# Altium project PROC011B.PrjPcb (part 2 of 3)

## Sheet PROC011B_PMIC.SchDoc: PMIC
size 431 x 279 mm; Date: Not shown in title block; ApprovedBy: Not shown in title block; CheckedBy: Not shown in title block; Author: Not shown in title block; CompanyName: Not shown in title block; Engineer: Not shown in title block; Organization: Not shown in title block; Address1: Not shown in title block; Address2: Not shown in title block; Address3: Not shown in title block; Address4: Not shown in title block; DocumentNumber: 1; Revision: Use project parameter SCH_Rev; SheetNumber: 8; SheetTotal: 17; PageSetup: Record=PageOptions¦CenterHorizontal=True¦CenterVertical=True¦PrintScale=1.00¦XCorrection=1.00¦YCorrection=1.00¦PrintKind=0¦BorderSize=5000000¦LeftOffset=0¦BottomOffset=0¦Orientation=2¦PaperLength=1000¦PaperWidth=1000¦Scale=100¦PaperSource=15¦PrintQuality=600¦MediaType=1¦DitherType=10¦PaperKind=Letter¦PrintScaleMode=1

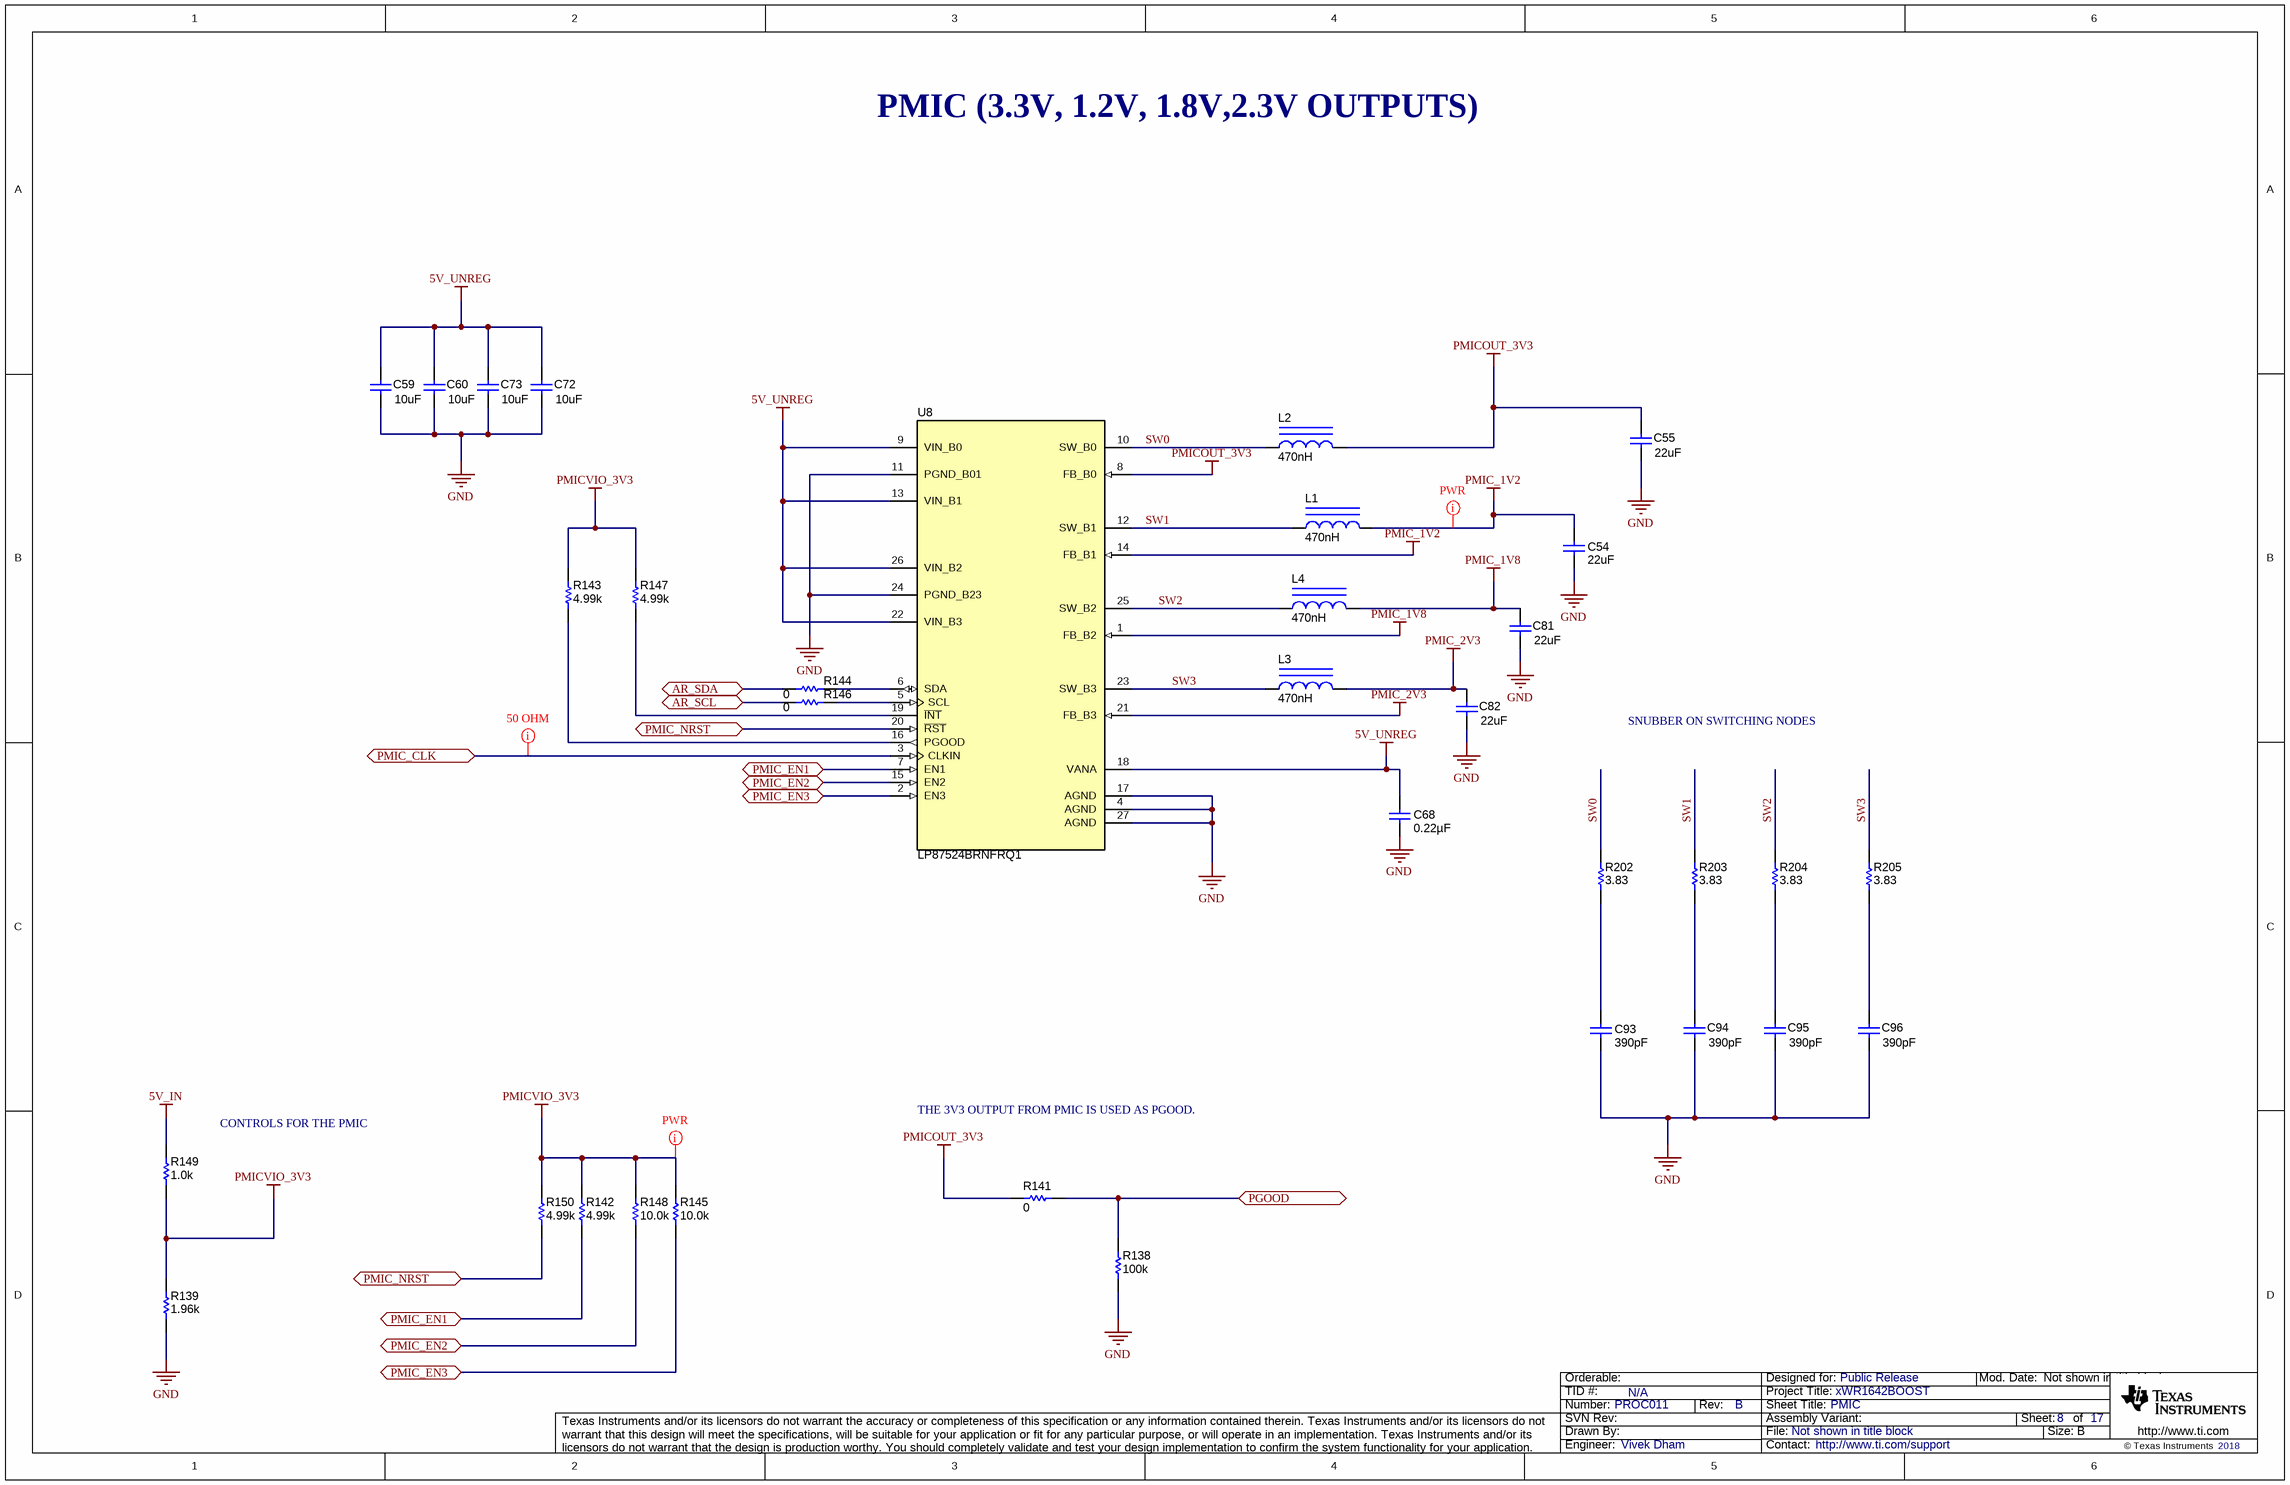
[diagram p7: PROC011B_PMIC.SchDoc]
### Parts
C54  ValueDisplayed: 22uF  [1206_180]  (hidden comment: GCM31CR71A226KE02)
C55  ValueDisplayed: 22uF  [1206_180]  (hidden comment: GCM31CR71A226KE02)
C59  ValueDisplayed: 10uF  [0805_HV]  (hidden comment: GCM21BR71A106KE22L)
C60  ValueDisplayed: 10uF  [0805_HV]  (hidden comment: GCM21BR71A106KE22L)
C68  ValueDisplayed: 0.22µF  [0402L]  (hidden comment: GCM155R71C224KE02D)
C72  ValueDisplayed: 10uF  [0805_HV]  (hidden comment: GCM21BR71A106KE22L)
C73  ValueDisplayed: 10uF  [0805_HV]  (hidden comment: GCM21BR71A106KE22L)
C81  ValueDisplayed: 22uF  [1206_180]  (hidden comment: GCM31CR71A226KE02)
C82  ValueDisplayed: 22uF  [1206_180]  (hidden comment: GCM31CR71A226KE02)
C93  ValueDisplayed: 390pF  [0402L]  (hidden comment: CGA2B2NP01H391J050BA)
C94  ValueDisplayed: 390pF  [0402L]  (hidden comment: CGA2B2NP01H391J050BA)
C95  ValueDisplayed: 390pF  [0402L]  (hidden comment: CGA2B2NP01H391J050BA)
C96  ValueDisplayed: 390pF  [0402L]  (hidden comment: CGA2B2NP01H391J050BA)
L1  ValueDisplayed: 470nH  [DFE252012P]  (hidden comment: DFE252012P-R47M=P2)
L2  ValueDisplayed: 470nH  [DFE252012P]  (hidden comment: DFE252012P-R47M=P2)
L3  ValueDisplayed: 470nH  [DFE252012P]  (hidden comment: DFE252012P-R47M=P2)
L4  ValueDisplayed: 470nH  [DFE252012P]  (hidden comment: DFE252012P-R47M=P2)
R138  ValueDisplayed: 100k  [0402L]  (hidden comment: CRCW0402100KFKED)
R139  ValueDisplayed: 1.96k  [0402L]  (hidden comment: CRCW04021K96FKED)
R141  ValueDisplayed: 0  [0402L]  (hidden comment: ERJ-2GE0R00X)
R142  ValueDisplayed: 4.99k  [0402L]  (hidden comment: ERJ-2RKF4991X)
R143  ValueDisplayed: 4.99k  [0402L]  (hidden comment: CRCW04024K99FKED)
R144  ValueDisplayed: 0  [0201_Silk]  (hidden comment: CRCW02010000Z0ED)
R145  ValueDisplayed: 10.0k  [0402L]  (hidden comment: CRCW040210K0FKED)
R146  ValueDisplayed: 0  [0201_Silk]  (hidden comment: CRCW02010000Z0ED)
R147  ValueDisplayed: 4.99k  [0402L]  (hidden comment: CRCW04024K99FKED)
R148  ValueDisplayed: 10.0k  [0402L]  (hidden comment: CRCW040210K0FKED)
R149  ValueDisplayed: 1.0k  [0402L]  (hidden comment: ERJ-2GEJ102X)
R150  ValueDisplayed: 4.99k  [0402L]  (hidden comment: ERJ-2RKF4991X)
R202  ValueDisplayed: 3.83  [0402L]  (hidden comment: CRCW04023R83FKED)
R203  ValueDisplayed: 3.83  [0402L]  (hidden comment: CRCW04023R83FKED)
R204  ValueDisplayed: 3.83  [0402L]  (hidden comment: CRCW04023R83FKED)
R205  ValueDisplayed: 3.83  [0402L]  (hidden comment: CRCW04023R83FKED)
U8  LP87524BRNFRQ1  [RNF0026C]

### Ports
AR_SCL, AR_SDA, PGOOD, PMIC_CLK, PMIC_EN1, PMIC_EN2, PMIC_EN3, PMIC_NRST

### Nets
5V_IN: R149.2
5V_UNREG: C59.2 C60.2 C68.2 C72.2 C73.2 U8.9(VIN_B0) U8.13(VIN_B1) U8.18(VANA) U8.22(VIN_B3) U8.26(VIN_B2)
GND: C54.1 C55.1 C59.1 C60.1 C68.1 C72.1 C73.1 C81.1 C82.1 C93.1 C94.1 C95.1 C96.1 R138.1 R139.1 U8.4(AGND) U8.11(PGND_B01) U8.17(AGND) U8.24(PGND_B23) U8.27(AGND)
PMIC_1V2: C54.2 L1.2 U8.14(FB_B1)
PMIC_1V8: C81.2 L4.2 U8.1(FB_B2)
PMIC_2V3: C82.2 L3.2 U8.21(FB_B3)
PMICOUT_3V3: C55.2 L2.2 R141.1 U8.8(FB_B0)
PMICVIO_3V3: R139.2 R142.2 R143.2 R145.2 R147.2 R148.2 R149.1 R150.1
AR_SCL: R146.1 ; port AR_SCL
AR_SDA: R144.2 ; port AR_SDA
PGOOD: R138.2 R141.2 ; port PGOOD
PMIC_CLK: U8.3(CLKIN) ; port PMIC_CLK
PMIC_EN1: R142.1 U8.7(EN1) ; port PMIC_EN1
PMIC_EN2: R148.1 U8.15(EN2) ; port PMIC_EN2
PMIC_EN3: R145.1 U8.2(EN3) ; port PMIC_EN3
PMIC_NRST: R150.2 U8.20(~{RST}) ; port PMIC_NRST
SW0: L2.1 R202.2 U8.10(SW_B0)
SW1: L1.1 R203.2 U8.12(SW_B1)
SW2: L4.1 R204.2 U8.25(SW_B2)
SW3: L3.1 R205.2 U8.23(SW_B3)
NetC93_2: C93.2 R202.1
NetC94_2: C94.2 R203.1
NetC95_2: C95.2 R204.1
NetC96_2: C96.2 R205.1
NetR143_1: R143.1 U8.16(PGOOD)
NetR144_1: R144.1 U8.6(SDA)
NetR146_2: R146.2 U8.5(SCL)
NetR147_1: R147.1 U8.19(~{INT})

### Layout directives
net class 50_OHM: PMIC_CLK
net class PWR: PMIC_1V2, PMICVIO_3V3

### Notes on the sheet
- PMIC (3.3V, 1.2V, 1.8V,2.3V OUTPUTS)
- SNUBBER ON SWITCHING NODES
- CONTROLS FOR THE PMIC
- THE 3V3 OUTPUT FROM PMIC IS USED AS PGOOD.

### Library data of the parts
C54 = CMP-0008811-2: CAP, CERM, 22 uF, 10 V, +/- 10%, X7R, AEC-Q200 Grade 1, 1206; Manufacturer: MuRata; TaMin_C: -55°C; Polarized: N; SizeAreaWB_mm2: 10.92; Value1: Unknown; U/M: EA; Value: 22uF; TaMax_C: 125°C; SizeZ_mm: 1.8; SizeX_mm: 3.2; SizeY_mm: 1.6; Cap_Case: 1206; Value2: 10V; SizeArea_mm2: 5.12; CompType: Capacitor; AEC Qualified: Y; Cap_F: 22µF; AEC Grade: 1; AEC Category: Q200
C55 C81 C82 = CMP-0008811-2: CAP, CERM, 22 uF, 10 V, +/- 10%, X7R, AEC-Q200 Grade 1, 1206; Manufacturer: MuRata; TaMin_C: -55°C; Polarized: N; SizeAreaWB_mm2: 10.92; Value1: Unknown; U/M: EA; Value: 22uF; TaMax_C: 125°C; SizeZ_mm: 1.8; SizeX_mm: 3.2; SizeY_mm: 1.6; Cap_Case: 1206; Value2: 10V; SizeArea_mm2: 5.12; AEC Qualified: Y; Cap_F: 22µF; AEC Grade: 1; AEC Category: Q200
C59 C60 C72 C73 = CMP-0008017-2: CAP, CERM, 10 uF, 10 V, +/- 10%, X7R, 0805; Manufacturer: MuRata; TaMin_C: -55°C; Polarized: N; SizeAreaWB_mm2: 6.75; Value1: Unknown; U/M: EA; Value: 10uF; TaMax_C: 125°C; SizeZ_mm: 1.45; SizeX_mm: 2; SizeY_mm: 1.25; Cap_Case: 0805; Value2: 10V; SizeArea_mm2: 2.5; CompType: Capacitor; Cap_F: 10µF; AEC Category: Q200
C68 = CMP-0078265-1: CAP, CERM, 0.22 µF, 16 V,+/- 10%, X7R, AEC-Q200 Grade 1, 0402; Manufacturer: MuRata; TaMin_C: -55°C; Polarized: N; SizeAreaWB_mm2: 3; U/M: EA; Value: 0.22uF; TaMax_C: 125°C; SizeZ_mm: 0.6; SizeX_mm: 1; SizeY_mm: 0.5; Cap_Case: 0402; Value2: 16V; CompType: Capacitor; AEC Qualified: Y; Cap_F: 220nF; AEC Category: Q200
C93-C96 = CMP-0078223-1: CAP, CERM, 390 pF, 50 V,+/- 5%, C0G/NP0, AEC-Q200 Grade 0, 0402; Manufacturer: TDK; TaMin_C: -55°C; Polarized: N; SizeAreaWB_mm2: 3; U/M: EA; Value: 390pF; TaMax_C: 150°C; SizeZ_mm: 0.6; SizeX_mm: 1; SizeY_mm: 0.5; Cap_Case: 0402; Value2: 50V; AEC Qualified: Y; AEC Grade: 0; AEC Category: Q200
L1-L4 = CMP-0058946-1: Inductor, Shielded, 470 nH, 4.7 A, 0.021 ohm, SMD; Manufacturer: MuRata Toko; Isat: 6.4A @ 30% inductance drop; Irms: 4.7A @ 40C rise; SizeAreaWB_mm2: 10.5; DCR_ohm: 0.021; Value: 470nH; Imax_A: 4.7A; SizeZ_mm: 1.2; SizeX_mm: 2.5; SizeY_mm: 2; SizeArea_mm2: 5; AEC Category: Q200
R138 = CMP-0025950-2: RES, 100 k, 1%, 0.063 W, 0402; Manufacturer: Vishay-Dale; Power_W: 63mW; TempCo: 100 ppm/C; U/M: EA; Value: 100k; EIA_Code: E96; SizeX_mm: 1; SizeY_mm: 0.5; SizeZ_mm: 0.6; Value2: 0.063W; VDC_V: 50V; AEC Category: Q200
R139 = CMP-0026099-1: RES, 1.96 k, 1%, 0.063 W, 0402; Manufacturer: Vishay-Dale; Power_W: 63mW; TempCo: 100 ppm/C; Value_Code: 1k96; U/M: EA; Value: 1.96k; EIA_Code: E96; SizeX_mm: 1; SizeY_mm: 0.5; SizeZ_mm: 0.6; Value2: 0.063W; CompType: Resistor; VDC_V: 50V; AEC Category: Q200
R141 = CMP-0026992-2: RES, 0, 5%, 0.063 W, 0402; Manufacturer: Panasonic; Power_W: 63mW; TempCo: 600 ppm/C; Value_Code: 0000; U/M: EA; Value: 0; EIA_Code: E24; SizeX_mm: 1; SizeY_mm: 0.5; SizeZ_mm: 0.6; Value2: 0.063W; VDC_V: 50V; AEC Category: Q200
R142 R150 = CMP-0026701-1: RES, 4.99 k, 1%, 0.1 W, AEC-Q200 Grade 0, 0402; Manufacturer: Panasonic; Power_W: 100mW; TempCo: 100 ppm/C; Value_Code: 4k99; U/M: EA; Value: 4.99k; EIA_Code: E96; SizeX_mm: 1; SizeY_mm: 0.5; SizeZ_mm: 0.6; Value2: 0.1W; AEC Qualified: Y; VDC_V: 50V; AEC Grade: 0; AEC Category: Q200
R143 R147 = CMP-0026414-1: RES, 4.99 k, 1%, 0.063 W, 0402; Manufacturer: Vishay-Dale; Power_W: 63mW; TempCo: 100 ppm/C; Value_Code: 4k99; U/M: EA; Value: 4.99k; EIA_Code: E96; SizeX_mm: 1; SizeY_mm: 0.5; SizeZ_mm: 0.6; Value2: 0.063W; VDC_V: 50V; AEC Category: Q200
R144 R146 = CMP-0027008-3: RES, 0, 5%, 0.05 W, 0201; Manufacturer: Vishay-Dale; Power_W: 50mW; TempCo: ppm/C; Value_Code: 0000; U/M: EA; Value: 0; EIA_Code: E24; SizeX_mm: 0.6; SizeY_mm: 0.3; SizeZ_mm: 0.26; Value2: 0.05W; SizeArea_mm2: 0.18; AEC Qualified: N; AEC Category: Q200
R145 R148 = CMP-0025958-2: RES, 10.0 k, 1%, 0.063 W, 0402; Manufacturer: Vishay-Dale; Power_W: 63mW; TempCo: 100 ppm/C; Value_Code: 10k0; U/M: EA; Value: 10.0k; EIA_Code: E96; Res_ohm: 10k; SizeX_mm: 1; SizeY_mm: 0.5; SizeZ_mm: 0.6; Value2: 0.063W; VDC_V: 50V; AEC Category: Q200
R149 = CMP-0078193-1: RES, 1.0 k, 5%, 0.1 W, AEC-Q200 Grade 0, 0402; Manufacturer: Panasonic; Value_Code: 1k00; SizeArea_mm2: 0.5; AEC Qualified: Y; AEC Category: Q200; Res_ohm: 1k; Value: 1.0k; SizeZ_mm: 0.6; Green_REACh: Passed; EIA_Code: E24; TempCo: 200 ppm/C; AEC Grade: 0; Power_W: 100mW; VDC_V: 50V; Value2: 0.1W; Green_Lifecycle: Active; U/M: EA; SizeX_mm: 1
R202-R205 = CMP-0026363-1: RES, 3.83, 1%, 0.063 W, 0402; Manufacturer: Vishay-Dale; Power_W: 63mW; TempCo: 100 ppm/C; Value_Code: 3R83; U/M: EA; Value: 3.83; EIA_Code: E96; SizeX_mm: 1; SizeY_mm: 0.5; SizeZ_mm: 0.6; Value2: 0.063W; VDC_V: 50V; AEC Category: Q200
U8 = CMP-0013883-2: Four-Phase 2.5-A-per-Phase Buck Converter With Integrated Switches, RNF0026C (VQFN-HR-26); Manufacturer: Texas Instruments; SizeX_mm: 4; SizeY_mm: 4.5; CompType: IC; SizeZ_mm: 0.9; SizeArea_mm2: 18; SizeAreaWB_mm2: 27.5; U/M: EA

## Sheet PROC011B_QSPI flash section.SchDoc: QSPI flash section
size 431 x 279 mm; Date: Not shown in title block; ApprovedBy: Not shown in title block; CheckedBy: Not shown in title block; Author: Not shown in title block; CompanyName: Not shown in title block; Engineer: Not shown in title block; Organization: Not shown in title block; Address1: Not shown in title block; Address2: Not shown in title block; Address3: Not shown in title block; Address4: Not shown in title block; DocumentNumber: 1; Revision: Use project parameter SCH_Rev; SheetNumber: 9; SheetTotal: 17; PageSetup: Record=PageOptions¦CenterHorizontal=True¦CenterVertical=True¦PrintScale=1.00¦XCorrection=1.00¦YCorrection=1.00¦PrintKind=0¦BorderSize=5000000¦LeftOffset=0¦BottomOffset=0¦Orientation=2¦PaperLength=1000¦PaperWidth=1000¦Scale=100¦PaperSource=15¦PrintQuality=600¦MediaType=1¦DitherType=10¦PaperKind=Letter¦PrintScaleMode=1

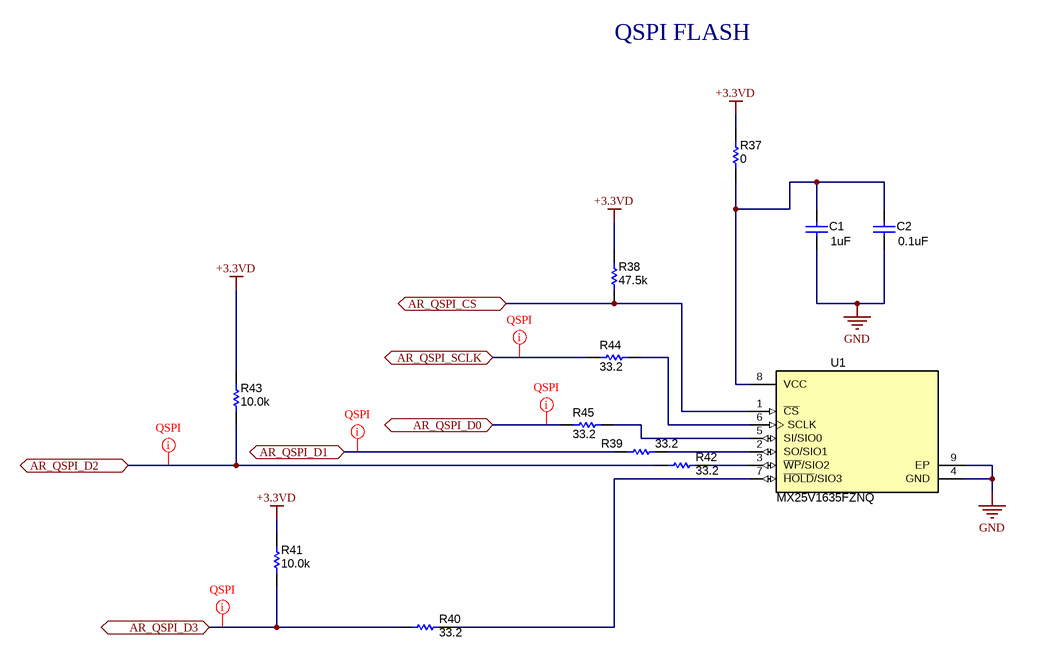
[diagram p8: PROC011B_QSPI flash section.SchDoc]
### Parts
C1  ValueDisplayed: 1uF  [0603]  (hidden comment: GCM188R71C105KA64D)
C2  ValueDisplayed: 0.1uF  [0402L]  (hidden comment: CGA2B3X7R1H104K050BB)
R37  ValueDisplayed: 0  [0402L]  (hidden comment: ERJ-2GE0R00X)
R38  ValueDisplayed: 47.5k  [0402L]  (hidden comment: CRCW040247K5FKED)
R39  ValueDisplayed: 33.2  [0201_Silk]  (hidden comment: CRCW020133R2FNED)
R40  ValueDisplayed: 33.2  [0201_Silk]  (hidden comment: CRCW020133R2FNED)
R41  ValueDisplayed: 10.0k  [0402L]  (hidden comment: CRCW040210K0FKED)
R42  ValueDisplayed: 33.2  [0201_Silk]  (hidden comment: CRCW020133R2FNED)
R43  ValueDisplayed: 10.0k  [0402L]  (hidden comment: CRCW040210K0FKED)
R44  ValueDisplayed: 33.2  [0201_Silk]  (hidden comment: CRCW020133R2FNED)
R45  ValueDisplayed: 33.2  [0201_Silk]  (hidden comment: CRCW020133R2FNED)
U1  MX25V1635FZNQ  [WSON-8L_6x5MM_EP]

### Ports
AR_QSPI_CS, AR_QSPI_D0, AR_QSPI_D1, AR_QSPI_D2, AR_QSPI_D3, AR_QSPI_SCLK

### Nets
+3.3VD: R37.1 R38.2 R41.2 R43.2
GND: C1.1 C2.1 U1.4(GND) U1.9(EP)
AR_QSPI_CS: R38.1 U1.1(~{CS}) ; port AR_QSPI_CS
AR_QSPI_D0: R45.2 ; port AR_QSPI_D0
AR_QSPI_D1: R39.1 ; port AR_QSPI_D1
AR_QSPI_D2: R42.1 R43.1 ; port AR_QSPI_D2
AR_QSPI_D3: R40.2 R41.1 ; port AR_QSPI_D3
AR_QSPI_SCLK: R44.2 ; port AR_QSPI_SCLK
NetC1_2: C1.2 C2.2 R37.2 U1.8(VCC)
NetR39_2: R39.2 U1.2(SO/SIO1)
NetR40_1: R40.1 U1.7(~{HOLD}/SIO3)
NetR42_2: R42.2 U1.3(~{WP}/SIO2)
NetR44_1: R44.1 U1.6(SCLK)
NetR45_1: R45.1 U1.5(SI/SIO0)

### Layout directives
net class QSPI: AR_QSPI_D0, AR_QSPI_D1, AR_QSPI_D2, AR_QSPI_D3, AR_QSPI_SCLK

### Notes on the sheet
- QSPI FLASH

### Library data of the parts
C1 = CMP-0007136-5: CAP, CERM, 1 uF, 16 V, +/- 10%, X7R, AEC-Q200 Grade 1, 0603; Manufacturer: MuRata; TaMin_C: -55°C; Polarized: N; SizeAreaWB_mm2: 4.68; Value1: Unknown; U/M: EA; Value: 1uF; TaMax_C: 125°C; SizeZ_mm: 1; SizeX_mm: 1.6; SizeY_mm: 0.8; Value2: 16V; SizeArea_mm2: 1.28; AEC Qualified: Y; Cap_F: 1µF; AEC Category: Q200
C2 = CMP-0006325-2: CAP, CERM, 0.1 uF, 50 V, +/- 10%, X7R, AEC-Q200 Grade 1, 0402; Manufacturer: TDK; TaMin_C: -55°C; ESR_ohm: 0.039064; Polarized: N; SizeAreaWB_mm2: 3; Value1: 0.039064 ohm; U/M: EA; Value: 0.1uF; TaMax_C: 125°C; SizeZ_mm: 0.6; SizeX_mm: 1; SizeY_mm: 0.5; Cap_Case: 0402; Value2: 50V; AEC Qualified: Y; Cap_F: 100nF; IRMS_A: 8.14669dA; AEC Category: Q200
R37 = CMP-0026992-2: as R141 on sheet PROC011B_PMIC
R38 = CMP-0026395-1: RES, 47.5 k, 1%, 0.063 W, 0402; Manufacturer: Vishay-Dale; Power_W: 63mW; TempCo: 100 ppm/C; Value_Code: 47k5; U/M: EA; Value: 47.5k; EIA_Code: E96; SizeX_mm: 1; SizeY_mm: 0.5; SizeZ_mm: 0.6; Value2: 0.063W; VDC_V: 50V; AEC Category: Q200
R39 R40 R42 R44 R45 = CMP-0027275-2: RES, 33.2, 1%, 0.05 W, 0201; Manufacturer: Vishay-Dale; Power_W: 50mW; TempCo: 200 ppm/C; Value_Code: 33R2; U/M: EA; Value: 33.2; EIA_Code: E96; SizeX_mm: 0.6; SizeY_mm: 0.3; SizeZ_mm: 0.26; Value2: 0.05W; SizeArea_mm2: 0.18; AEC Qualified: N; AEC Category: Q200
R41 R43 = CMP-0025958-2: as R145 on sheet PROC011B_PMIC
U1 = CMP-0079267-1: 2.3V-3.6V, 16M-BIT [x 1/x 2/x 4] CMOS FLASH Memory, WSON-8; Manufacturer: Macronix International Co., LTD; SizeArea_mm2: 30; SizeAreaWB_mm2: 56; SizeY_mm: 5; SizeZ_mm: 0.8; SizeX_mm: 6

## Sheet PROC011B_LP Connector.SchDoc: LP Connector
size 431 x 279 mm; Date: Not shown in title block; ApprovedBy: Not shown in title block; CheckedBy: Not shown in title block; Author: Not shown in title block; CompanyName: Not shown in title block; Engineer: Not shown in title block; Organization: Not shown in title block; Address1: Not shown in title block; Address2: Not shown in title block; Address3: Not shown in title block; Address4: Not shown in title block; DocumentNumber: 1; Revision: Use project parameter SCH_Rev; SheetNumber: 10; SheetTotal: 17; PageSetup: Record=PageOptions¦CenterHorizontal=True¦CenterVertical=True¦PrintScale=1.00¦XCorrection=1.00¦YCorrection=1.00¦PrintKind=0¦BorderSize=5000000¦LeftOffset=0¦BottomOffset=0¦Orientation=2¦PaperLength=1000¦PaperWidth=1000¦Scale=100¦PaperSource=15¦PrintQuality=600¦MediaType=1¦DitherType=10¦PaperKind=Letter¦PrintScaleMode=1

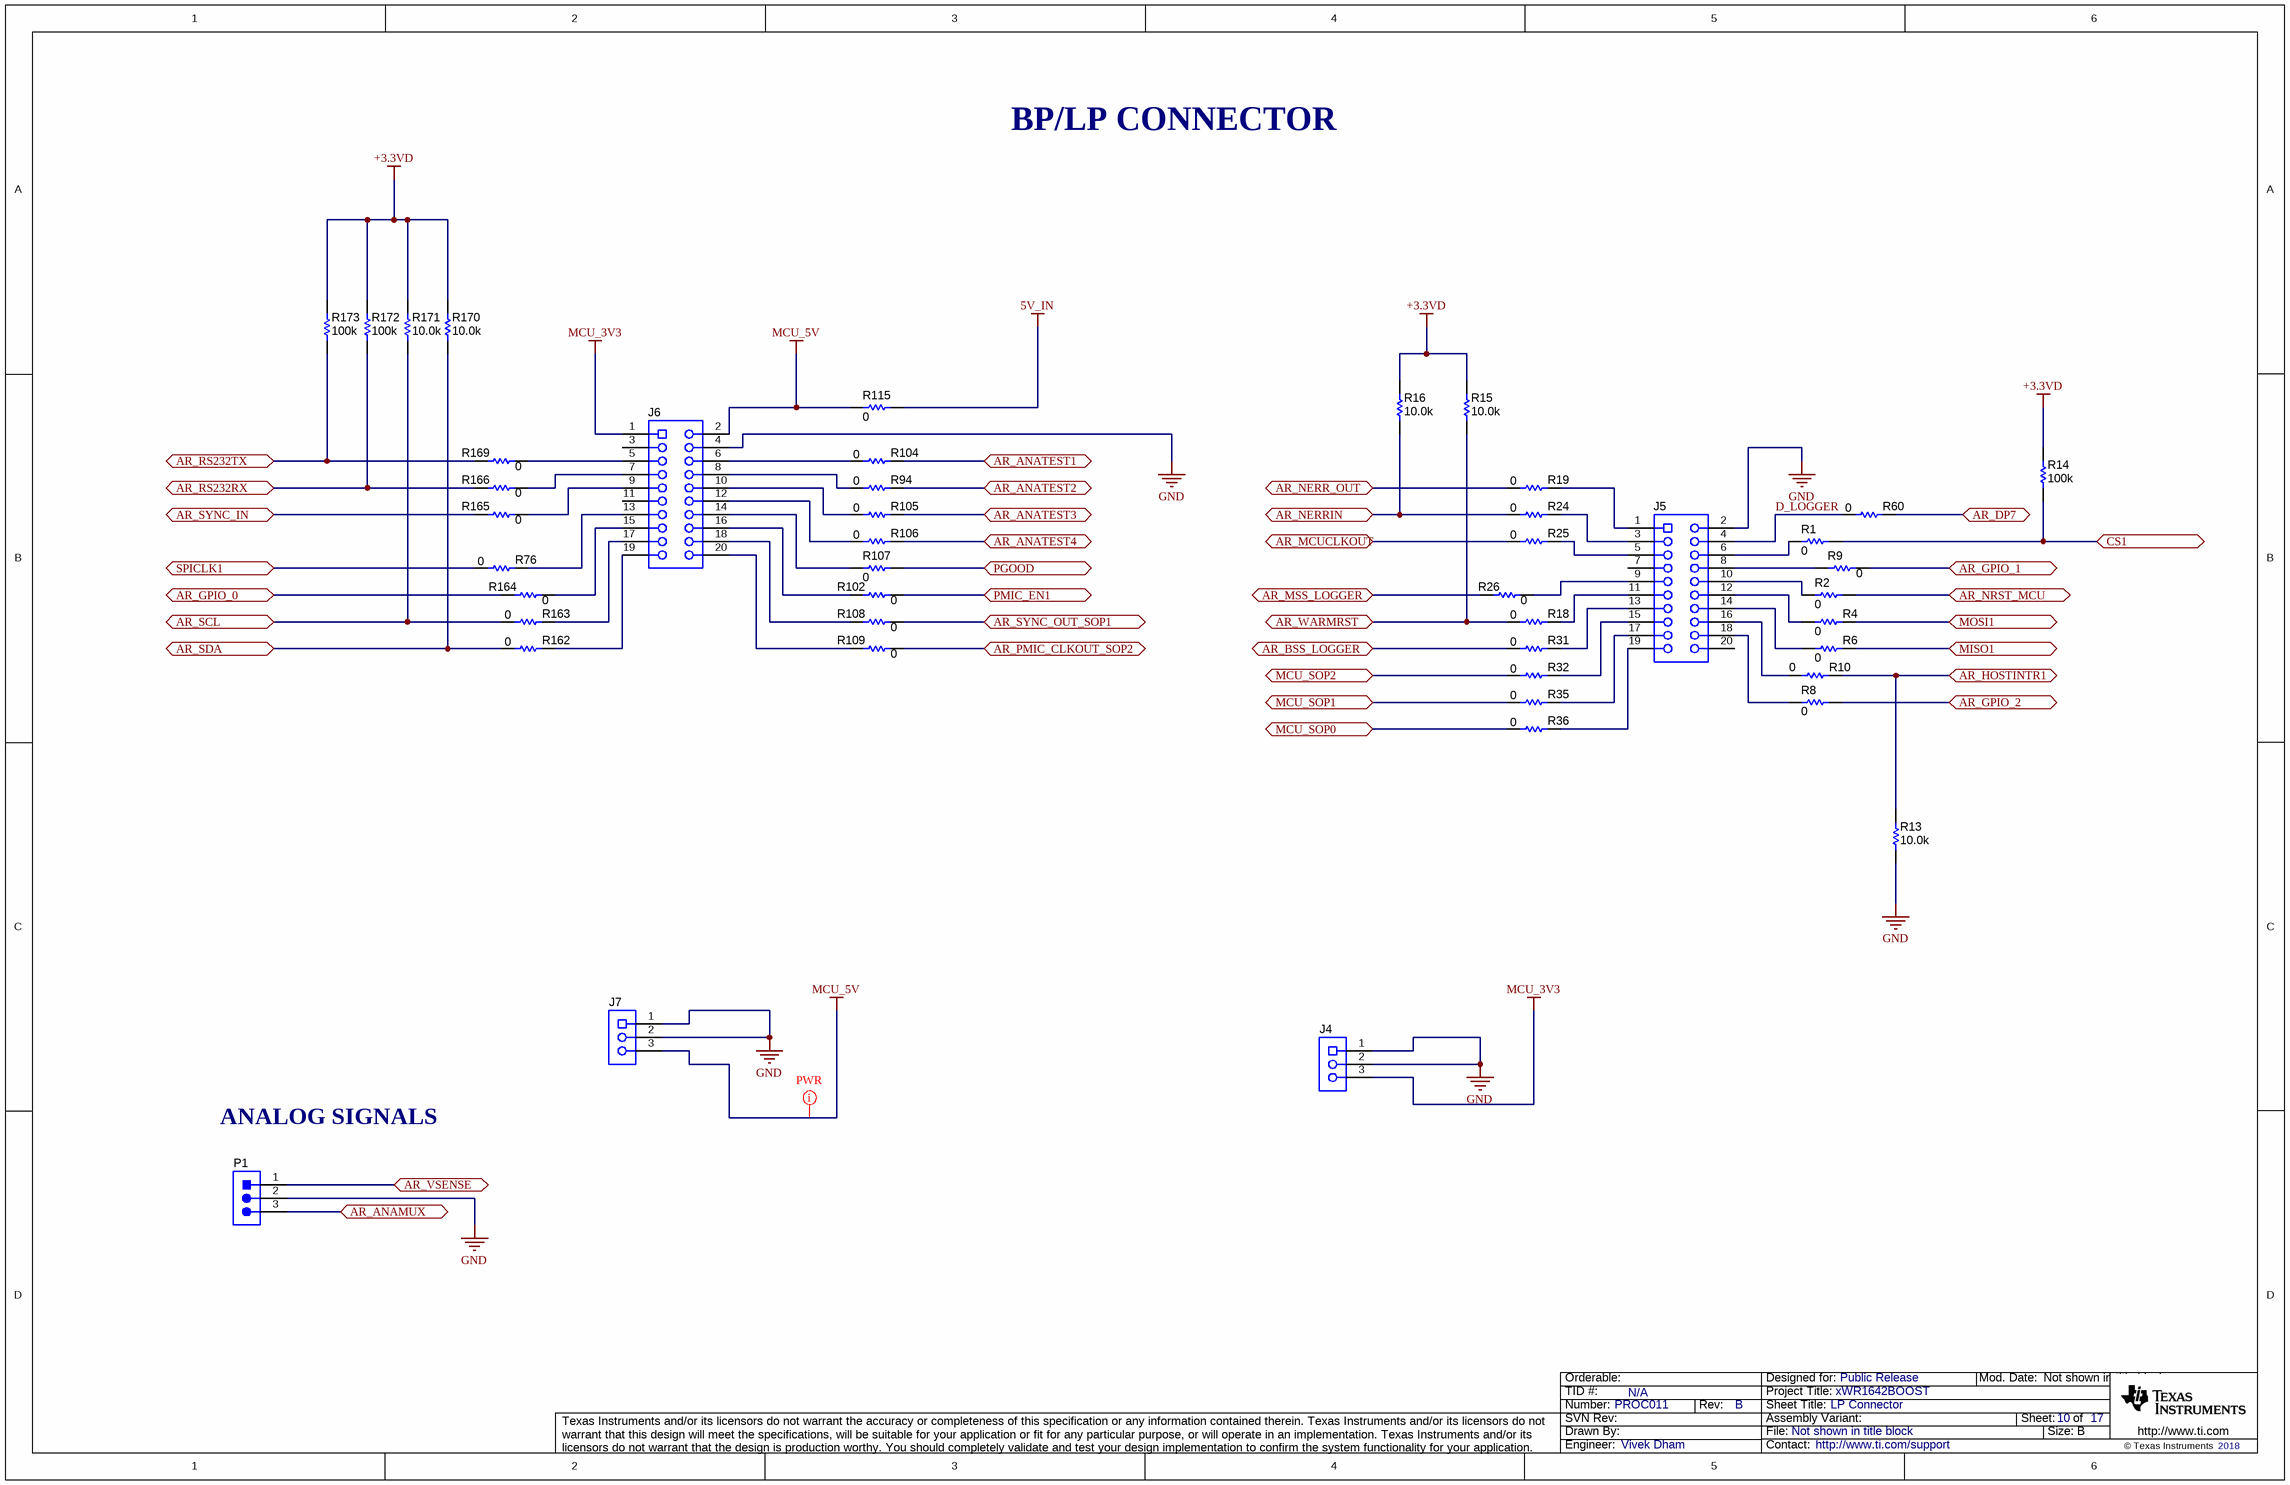
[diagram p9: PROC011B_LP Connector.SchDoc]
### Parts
J4  SSM-103-S-SV  [Samtec_SSM-103-x-SV]  (value not drawn)
J5  SSM-110-S-DV  [Samtec_SSM-110-x-DV]  (value not drawn)
J6  SSM-110-S-DV  [Samtec_SSM-110-x-DV]  (value not drawn)
J7  SSM-103-S-SV  [Samtec_SSM-103-x-SV]  (value not drawn)
P1  TSW-103-07-T-S  [Samtec_TSW-103-07-T-S]  (value not drawn)
R1  ValueDisplayed: 0  [0201_Silk]  (hidden comment: CRCW02010000Z0ED)
R2  ValueDisplayed: 0  [0201_Silk]  (hidden comment: CRCW02010000Z0ED)
R4  ValueDisplayed: 0  [0201_Silk]  (hidden comment: CRCW02010000Z0ED)
R6  ValueDisplayed: 0  [0201_Silk]  (hidden comment: CRCW02010000Z0ED)
R8  ValueDisplayed: 0  [0201_Silk]  (hidden comment: CRCW02010000Z0ED)
R9  ValueDisplayed: 0  [0201_Silk]  (hidden comment: CRCW02010000Z0ED)
R10  ValueDisplayed: 0  [0201_Silk]  (hidden comment: CRCW02010000Z0ED)
R13  ValueDisplayed: 10.0k  [0402L]  (hidden comment: CRCW040210K0FKED)
R14  ValueDisplayed: 100k  [0402L]  (hidden comment: CRCW0402100KFKED)
R15  ValueDisplayed: 10.0k  [0402L]  (hidden comment: CRCW040210K0FKED)
R16  ValueDisplayed: 10.0k  [0402L]  (hidden comment: CRCW040210K0FKED)
R18  ValueDisplayed: 0  [0201_Silk]  (hidden comment: CRCW02010000Z0ED)
R19  ValueDisplayed: 0  [0201_Silk]  (hidden comment: CRCW02010000Z0ED)
R24  ValueDisplayed: 0  [0201_Silk]  (hidden comment: CRCW02010000Z0ED)
R25  ValueDisplayed: 0  [0201_Silk]  (hidden comment: CRCW02010000Z0ED)
R26  ValueDisplayed: 0  [0201_Silk]  (hidden comment: CRCW02010000Z0ED)
R31  ValueDisplayed: 0  [0201_Silk]  (hidden comment: CRCW02010000Z0ED)
R32  ValueDisplayed: 0  [0201_Silk]  (hidden comment: CRCW02010000Z0ED)
R35  ValueDisplayed: 0  [0201_Silk]  (hidden comment: CRCW02010000Z0ED)
R36  ValueDisplayed: 0  [0201_Silk]  (hidden comment: CRCW02010000Z0ED)
R60  ValueDisplayed: 0  [0201_Silk]  (hidden comment: CRCW02010000Z0ED)
R76  ValueDisplayed: 0  [0201_Silk]  (hidden comment: CRCW02010000Z0ED)
R94  ValueDisplayed: 0  [0201_Silk]  (hidden comment: CRCW02010000Z0ED)
R102  ValueDisplayed: 0  [0201_Silk]  (hidden comment: CRCW02010000Z0ED)
R104  ValueDisplayed: 0  [0201_Silk]  (hidden comment: CRCW02010000Z0ED)
R105  ValueDisplayed: 0  [0201_Silk]  (hidden comment: CRCW02010000Z0ED)
R106  ValueDisplayed: 0  [0201_Silk]  (hidden comment: CRCW02010000Z0ED)
R107  ValueDisplayed: 0  [0402L]  (hidden comment: ERJ-2GE0R00X)
R108  ValueDisplayed: 0  [0201_Silk]  (hidden comment: CRCW02010000Z0ED)
R109  ValueDisplayed: 0  [0201_Silk]  (hidden comment: CRCW02010000Z0ED)
R115  ValueDisplayed: 0  [2010]  (hidden comment: CRCW20100000Z0EF)
R162  ValueDisplayed: 0  [0201_Silk]  (hidden comment: CRCW02010000Z0ED)
R163  ValueDisplayed: 0  [0201_Silk]  (hidden comment: CRCW02010000Z0ED)
R164  ValueDisplayed: 0  [0201_Silk]  (hidden comment: CRCW02010000Z0ED)
R165  ValueDisplayed: 0  [0201_Silk]  (hidden comment: CRCW02010000Z0ED)
R166  ValueDisplayed: 0  [0201_Silk]  (hidden comment: CRCW02010000Z0ED)
R169  ValueDisplayed: 0  [0201_Silk]  (hidden comment: CRCW02010000Z0ED)
R170  ValueDisplayed: 10.0k  [0402L]  (hidden comment: CRCW040210K0FKED)
R171  ValueDisplayed: 10.0k  [0402L]  (hidden comment: CRCW040210K0FKED)
R172  ValueDisplayed: 100k  [0402L]  (hidden comment: CRCW0402100KFKED)
R173  ValueDisplayed: 100k  [0402L]  (hidden comment: CRCW0402100KFKED)

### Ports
AR_ANAMUX, AR_ANATEST1, AR_ANATEST2, AR_ANATEST3, AR_ANATEST4, AR_BSS_LOGGER, AR_DP7, AR_GPIO_0, AR_GPIO_1, AR_GPIO_2, AR_HOSTINTR1, AR_MCUCLKOUT, AR_MSS_LOGGER, AR_NERR_OUT, AR_NERRIN, AR_NRST_MCU, AR_PMIC_CLKOUT_SOP2, AR_RS232RX, AR_RS232TX, AR_SCL, AR_SDA, AR_SYNC_IN, AR_SYNC_OUT_SOP1, AR_VSENSE, AR_WARMRST, CS1, MCU_SOP0, MCU_SOP1, MCU_SOP2, MISO1, MOSI1, PGOOD, PMIC_EN1, SPICLK1

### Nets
5V_IN: R115.2
+3.3VD: R14.2 R15.2 R16.2 R170.2 R171.2 R172.2 R173.2
GND: J4.1 J4.2 J5.2 J6.4 J7.1 J7.2 P1.2 R13.1
MCU_3V3: J4.3 J6.1
MCU_5V: J6.2 J7.3 R115.1
AR_ANAMUX: P1.3 ; port AR_ANAMUX
AR_ANATEST1: R104.2 ; port AR_ANATEST1
AR_ANATEST2: R94.2 ; port AR_ANATEST2
AR_ANATEST3: R105.2 ; port AR_ANATEST3
AR_ANATEST4: R106.2 ; port AR_ANATEST4
AR_BSS_LOGGER: R31.1 ; port AR_BSS_LOGGER
AR_DP7: R60.2 ; port AR_DP7
AR_GPIO_0: R164.1 ; port AR_GPIO_0
AR_GPIO_1: R9.2 ; port AR_GPIO_1
AR_GPIO_2: R8.2 ; port AR_GPIO_2
AR_HOSTINTR1: R10.2 R13.2 ; port AR_HOSTINTR1
AR_MCUCLKOUT: R25.1 ; port AR_MCUCLKOUT
AR_MSS_LOGGER: R26.1 ; port AR_MSS_LOGGER
AR_NERR_OUT: R19.1 ; port AR_NERR_OUT
AR_NERRIN: R16.1 R24.1 ; port AR_NERRIN
AR_NRST_MCU: R2.2 ; port AR_NRST_MCU
AR_PMIC_CLKOUT_SOP2: R109.2 ; port AR_PMIC_CLKOUT_SOP2
AR_RS232RX: R166.1 R172.1 ; port AR_RS232RX
AR_RS232TX: R169.1 R173.1 ; port AR_RS232TX
AR_SCL: R163.1 R171.1 ; port AR_SCL
AR_SDA: R162.1 R170.1 ; port AR_SDA
AR_SYNC_IN: R165.1 ; port AR_SYNC_IN
AR_SYNC_OUT_SOP1: R108.2 ; port AR_SYNC_OUT_SOP1
AR_VSENSE: P1.1 ; port AR_VSENSE
AR_WARMRST: R15.1 R18.1 ; port AR_WARMRST
CS1: R1.2 R14.1 ; port CS1
D_LOGGER: J5.4 R60.1
MCU_SOP0: R36.1 ; port MCU_SOP0
MCU_SOP1: R35.1 ; port MCU_SOP1
MCU_SOP2: R32.1 ; port MCU_SOP2
MISO1: R6.2 ; port MISO1
MOSI1: R4.2 ; port MOSI1
PGOOD: R107.2 ; port PGOOD
PMIC_EN1: R102.2 ; port PMIC_EN1
SPICLK1: R76.1 ; port SPICLK1
NetJ5_1: J5.1 R19.2
NetJ5_3: J5.3 R24.2
NetJ5_5: J5.5 R25.2
NetJ5_6: J5.6 R1.1
NetJ5_8: J5.8 R9.1
NetJ5_9: J5.9 R26.2
NetJ5_10: J5.10 R2.1
NetJ5_11: J5.11 R18.2
NetJ5_12: J5.12 R4.1
NetJ5_13: J5.13 R31.2
NetJ5_14: J5.14 R6.1
NetJ5_15: J5.15 R32.2
NetJ5_16: J5.16 R10.1
NetJ5_17: J5.17 R35.2
NetJ5_18: J5.18 R8.1
NetJ5_19: J5.19 R36.2
NetJ6_5: J6.5 R169.2
NetJ6_6: J6.6 R104.1
NetJ6_7: J6.7 R166.2
NetJ6_8: J6.8 R94.1
NetJ6_9: J6.9 R165.2
NetJ6_10: J6.10 R105.1
NetJ6_12: J6.12 R106.1
NetJ6_13: J6.13 R76.2
NetJ6_14: J6.14 R107.1
NetJ6_15: J6.15 R164.2
NetJ6_16: J6.16 R102.1
NetJ6_17: J6.17 R163.2
NetJ6_18: J6.18 R108.1
NetJ6_19: J6.19 R162.2
NetJ6_20: J6.20 R109.1

Not connected (* = marked no-connect by the designer): J5 7 20; J6 3 11

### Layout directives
net class PWR: MCU_5V

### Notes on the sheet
- BP/LP CONNECTOR
- ANALOG SIGNALS

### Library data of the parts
J4 J7 = CMP-0078183-1: Receptacle, 2.54mm, 3x1, Gold with Tin tail, SMT; Manufacturer: Samtec; Pitch_mm: 2.54; Gender: Female; Cert_CSA: Y; Voltage_V: 405V; Current_A: 5.2A; Row_Count: 1; CompType: Socket Strip
J5 J6 = CMP-0078182-1: Receptacle, 2.54mm, 10x2, Gold with Tin tail, SMT; Manufacturer: Samtec; Pitch_mm: 2.54; Gender: Female; Cert_CSA: Y; Voltage_V: 405V; Current_A: 5.2A; Row_Count: 2; CompType: Socket Strip
P1 = CMP-0075530-1: Header, 2.54 mm, 3x1, Tin, TH; Manufacturer: Samtec; Pitch_mm: 2.54; Cert_VDE: N; Gender: Male; Cert_CSA: Y; Voltage_V: 550V; Green_REACh: Passed; Current_A: 6.3A; CT: False; Green_Lifecycle: Active; Row_Count: 1; CNHeader: True
R1 R2 R18 R19 R24 R25 R31 R32 R35 R36 R76 R94 R104-R106 R162 R163 = CMP-0027008-3: as R144 on sheet PROC011B_PMIC
R4 R6 R10 R60 = CMP-0027008-3: RES, 0, 5%, 0.05 W, 0201; Manufacturer: Vishay-Dale; Power_W: 50mW; TempCo: ppm/C; Value_Code: 0000; U/M: EA; Value: 0; EIA_Code: E24; SizeX_mm: 0.6; SizeY_mm: 0.3; SizeZ_mm: 0.26; Value2: 0.05W; SizeArea_mm2: 0.18; CompType: Resistor; AEC Qualified: N; AEC Category: Q200
R8 R9 R26 R102 R108 R109 R164-R166 R169 = CMP-0027008-3: RES, 0, 5%, 0.05 W, 0201; Manufacturer: Vishay-Dale; Power_W: 50mW; TempCo: ppm/C; Value_Code: 0000; U/M: EA; Value: 0; EIA_Code: E24; SizeX_mm: 0.6; SizeY_mm: 0.3; SizeZ_mm: 0.26; Value2: 0.05W; SizeArea_mm2: 0.18; CompType: Resistor; AEC Qualified: N; AEC Category: Q200; INSTALATION: DNP
R13 R15 R16 R170 R171 = CMP-0025958-2: as R145 on sheet PROC011B_PMIC
R14 R172 R173 = CMP-0025950-2: as R138 on sheet PROC011B_PMIC
R107 = CMP-0026992-2: as R141 on sheet PROC011B_PMIC
R115 = CMP-0016044-2: RES, 0, 5%, 0.75 W, AEC-Q200 Grade 0, 2010; Manufacturer: Vishay-Dale; Power_W: 750mW; TempCo: ppm/C; Value_Code: 0000; U/M: EA; Value: 0; EIA_Code: E24; SizeX_mm: 5; SizeY_mm: 2.5; SizeZ_mm: 1.66; Value2: 0.75W; SizeArea_mm2: 12.5; CompType: Resistor; AEC Qualified: Y; AEC Category: Q200; INSTALATION: DNP

## Sheet PROC011B_HD Connector.SchDoc: HD Connector
size 431 x 279 mm; Date: Not shown in title block; ApprovedBy: Not shown in title block; CheckedBy: Not shown in title block; Author: Not shown in title block; CompanyName: Not shown in title block; Engineer: Not shown in title block; Organization: Not shown in title block; Address1: Not shown in title block; Address2: Not shown in title block; Address3: Not shown in title block; Address4: Not shown in title block; DocumentNumber: 1; Revision: Use project parameter SCH_Rev; SheetNumber: 11; SheetTotal: 17; PageSetup: Record=PageOptions¦CenterHorizontal=True¦CenterVertical=True¦PrintScale=1.00¦XCorrection=1.00¦YCorrection=1.00¦PrintKind=0¦BorderSize=5000000¦LeftOffset=0¦BottomOffset=0¦Orientation=2¦PaperLength=1000¦PaperWidth=1000¦Scale=100¦PaperSource=15¦PrintQuality=600¦MediaType=1¦DitherType=10¦PrintScaleMode=1¦PaperKind=Letter

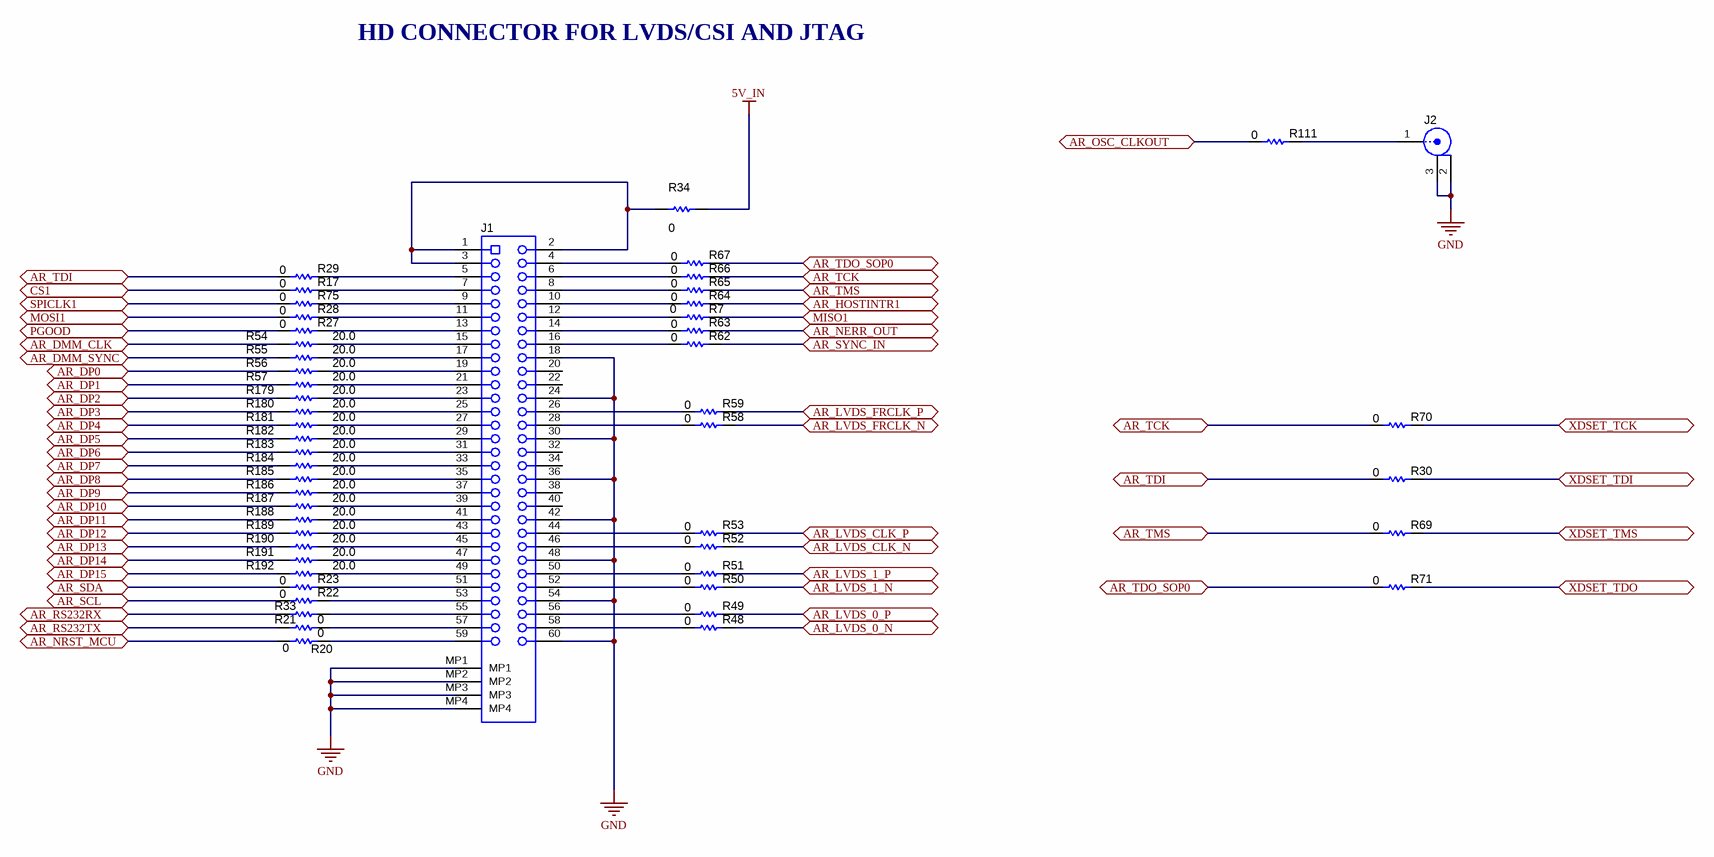
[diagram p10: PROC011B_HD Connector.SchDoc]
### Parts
J1  QSH-030-01-L-D-A  [Samtec_QSH-030-01-X-D-A]  (value not drawn)
J2  128-0711-201  [Johnson_128-0711-201]  (value not drawn)
R7  ValueDisplayed: 0  [0201_Silk]  (hidden comment: CRCW02010000Z0ED)
R17  ValueDisplayed: 0  [0201_Silk]  (hidden comment: CRCW02010000Z0ED)
R20  ValueDisplayed: 0  [0201_Silk]  (hidden comment: CRCW02010000Z0ED)
R21  ValueDisplayed: 0  [0201_Silk]  (hidden comment: CRCW02010000Z0ED)
R22  ValueDisplayed: 0  [0201_Silk]  (hidden comment: CRCW02010000Z0ED)
R23  ValueDisplayed: 0  [0201_Silk]  (hidden comment: CRCW02010000Z0ED)
R27  ValueDisplayed: 0  [0201_Silk]  (hidden comment: CRCW02010000Z0ED)
R28  ValueDisplayed: 0  [0201_Silk]  (hidden comment: CRCW02010000Z0ED)
R29  ValueDisplayed: 0  [0201_Silk]  (hidden comment: CRCW02010000Z0ED)
R30  ValueDisplayed: 0  [0201_Silk]  (hidden comment: CRCW02010000Z0ED)
R33  ValueDisplayed: 0  [0201_Silk]  (hidden comment: CRCW02010000Z0ED)
R34  ValueDisplayed: 0  [2010]  (hidden comment: CRCW20100000Z0EF)
R48  ValueDisplayed: 0  [0201_Silk]  (hidden comment: CRCW02010000Z0ED)
R49  ValueDisplayed: 0  [0201_Silk]  (hidden comment: CRCW02010000Z0ED)
R50  ValueDisplayed: 0  [0201_Silk]  (hidden comment: CRCW02010000Z0ED)
R51  ValueDisplayed: 0  [0201_Silk]  (hidden comment: CRCW02010000Z0ED)
R52  ValueDisplayed: 0  [0201_Silk]  (hidden comment: CRCW02010000Z0ED)
R53  ValueDisplayed: 0  [0201_Silk]  (hidden comment: CRCW02010000Z0ED)
R54  ValueDisplayed: 20.0  [0201_033]  (hidden comment: CRCW020120R0FNED)
R55  ValueDisplayed: 20.0  [0201_033]  (hidden comment: CRCW020120R0FNED)
R56  ValueDisplayed: 20.0  [0201_033]  (hidden comment: CRCW020120R0FNED)
R57  ValueDisplayed: 20.0  [0201_033]  (hidden comment: CRCW020120R0FNED)
R58  ValueDisplayed: 0  [0201_Silk]  (hidden comment: CRCW02010000Z0ED)
R59  ValueDisplayed: 0  [0201_Silk]  (hidden comment: CRCW02010000Z0ED)
R62  ValueDisplayed: 0  [0201_Silk]  (hidden comment: CRCW02010000Z0ED)
R63  ValueDisplayed: 0  [0201_Silk]  (hidden comment: CRCW02010000Z0ED)
R64  ValueDisplayed: 0  [0201_Silk]  (hidden comment: CRCW02010000Z0ED)
R65  ValueDisplayed: 0  [0201_Silk]  (hidden comment: CRCW02010000Z0ED)
R66  ValueDisplayed: 0  [0201_Silk]  (hidden comment: CRCW02010000Z0ED)
R67  ValueDisplayed: 0  [0201_Silk]  (hidden comment: CRCW02010000Z0ED)
R69  ValueDisplayed: 0  [0201_Silk]  (hidden comment: CRCW02010000Z0ED)
R70  ValueDisplayed: 0  [0201_Silk]  (hidden comment: CRCW02010000Z0ED)
R71  ValueDisplayed: 0  [0201_Silk]  (hidden comment: CRCW02010000Z0ED)
R75  ValueDisplayed: 0  [0201_Silk]  (hidden comment: CRCW02010000Z0ED)
R111  ValueDisplayed: 0  [0201_Silk]  (hidden comment: CRCW02010000Z0ED)
R179  ValueDisplayed: 20.0  [0201_033]  (hidden comment: CRCW020120R0FNED)
R180  ValueDisplayed: 20.0  [0201_033]  (hidden comment: CRCW020120R0FNED)
R181  ValueDisplayed: 20.0  [0201_033]  (hidden comment: CRCW020120R0FNED)
R182  ValueDisplayed: 20.0  [0201_033]  (hidden comment: CRCW020120R0FNED)
R183  ValueDisplayed: 20.0  [0201_033]  (hidden comment: CRCW020120R0FNED)
R184  ValueDisplayed: 20.0  [0201_033]  (hidden comment: CRCW020120R0FNED)
R185  ValueDisplayed: 20.0  [0201_033]  (hidden comment: CRCW020120R0FNED)
R186  ValueDisplayed: 20.0  [0201_033]  (hidden comment: CRCW020120R0FNED)
R187  ValueDisplayed: 20.0  [0201_033]  (hidden comment: CRCW020120R0FNED)
R188  ValueDisplayed: 20.0  [0201_033]  (hidden comment: CRCW020120R0FNED)
R189  ValueDisplayed: 20.0  [0201_033]  (hidden comment: CRCW020120R0FNED)
R190  ValueDisplayed: 20.0  [0201_033]  (hidden comment: CRCW020120R0FNED)
R191  ValueDisplayed: 20.0  [0201_033]  (hidden comment: CRCW020120R0FNED)
R192  ValueDisplayed: 20.0  [0201_033]  (hidden comment: CRCW020120R0FNED)

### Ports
AR_DMM_CLK, AR_DMM_SYNC, AR_DP0, AR_DP1, AR_DP2, AR_DP3, AR_DP4, AR_DP5, AR_DP6, AR_DP7, AR_DP8, AR_DP9, AR_DP10, AR_DP11, AR_DP12, AR_DP13, AR_DP14, AR_DP15, AR_HOSTINTR1, AR_LVDS_0_N, AR_LVDS_0_P, AR_LVDS_1_N, AR_LVDS_1_P, AR_LVDS_CLK_N, AR_LVDS_CLK_P, AR_LVDS_FRCLK_N, AR_LVDS_FRCLK_P, AR_NERR_OUT, AR_NRST_MCU, AR_OSC_CLKOUT, AR_RS232RX, AR_RS232TX, AR_SCL, AR_SDA, AR_SYNC_IN, AR_TCK, AR_TDI, AR_TDO_SOP0, AR_TMS, CS1, MISO1, MOSI1, PGOOD, SPICLK1, XDSET_TCK, XDSET_TDI, XDSET_TDO, XDSET_TMS

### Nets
5V_IN: R34.2
GND: J1.18 J1.24 J1.30 J1.36 J1.42 J1.48 J1.54 J1.60 J1.MP1 J1.MP2 J1.MP3 J1.MP4 J2.2 J2.3
AR_DMM_CLK: R54.1 ; port AR_DMM_CLK
AR_DMM_SYNC: R55.1 ; port AR_DMM_SYNC
AR_DP0: R56.1 ; port AR_DP0
AR_DP1: R57.1 ; port AR_DP1
AR_DP2: R179.1 ; port AR_DP2
AR_DP3: R180.1 ; port AR_DP3
AR_DP4: R181.1 ; port AR_DP4
AR_DP5: R182.1 ; port AR_DP5
AR_DP6: R183.1 ; port AR_DP6
AR_DP7: R184.1 ; port AR_DP7
AR_DP8: R185.1 ; port AR_DP8
AR_DP9: R186.1 ; port AR_DP9
AR_DP10: R187.1 ; port AR_DP10
AR_DP11: R188.1 ; port AR_DP11
AR_DP12: R189.1 ; port AR_DP12
AR_DP13: R190.1 ; port AR_DP13
AR_DP14: R191.1 ; port AR_DP14
AR_DP15: R192.1 ; port AR_DP15
AR_HOSTINTR1: R64.2 ; port AR_HOSTINTR1
AR_LVDS_0_N: R48.2 ; port AR_LVDS_0_N
AR_LVDS_0_P: R49.2 ; port AR_LVDS_0_P
AR_LVDS_1_N: R50.2 ; port AR_LVDS_1_N
AR_LVDS_1_P: R51.2 ; port AR_LVDS_1_P
AR_LVDS_CLK_N: R52.2 ; port AR_LVDS_CLK_N
AR_LVDS_CLK_P: R53.2 ; port AR_LVDS_CLK_P
AR_LVDS_FRCLK_N: R58.2 ; port AR_LVDS_FRCLK_N
AR_LVDS_FRCLK_P: R59.2 ; port AR_LVDS_FRCLK_P
AR_NERR_OUT: R63.2 ; port AR_NERR_OUT
AR_NRST_MCU: R20.1 ; port AR_NRST_MCU
AR_OSC_CLKOUT: R111.1 ; port AR_OSC_CLKOUT
AR_RS232RX: R33.1 ; port AR_RS232RX
AR_RS232TX: R21.1 ; port AR_RS232TX
AR_SCL: R22.1 ; port AR_SCL
AR_SDA: R23.1 ; port AR_SDA
AR_SYNC_IN: R62.2 ; port AR_SYNC_IN
AR_TCK: R66.2 R70.1 ; port AR_TCK
AR_TDI: R29.1 R30.1 ; port AR_TDI
AR_TDO_SOP0: R67.2 R71.1 ; port AR_TDO_SOP0
AR_TMS: R65.2 R69.1 ; port AR_TMS
CS1: R17.1 ; port CS1
MISO1: R7.2 ; port MISO1
MOSI1: R28.1 ; port MOSI1
PGOOD: R27.1 ; port PGOOD
SPICLK1: R75.1 ; port SPICLK1
XDSET_TCK: R70.2 ; port XDSET_TCK
XDSET_TDI: R30.2 ; port XDSET_TDI
XDSET_TDO: R71.2 ; port XDSET_TDO
XDSET_TMS: R69.2 ; port XDSET_TMS
NetJ1_1: J1.1 J1.2 J1.3 R34.1
NetJ1_4: J1.4 R67.1
NetJ1_5: J1.5 R29.2
NetJ1_6: J1.6 R66.1
NetJ1_7: J1.7 R17.2
NetJ1_8: J1.8 R65.1
NetJ1_9: J1.9 R75.2
NetJ1_10: J1.10 R64.1
NetJ1_11: J1.11 R28.2
NetJ1_12: J1.12 R7.1
NetJ1_13: J1.13 R27.2
NetJ1_14: J1.14 R63.1
NetJ1_15: J1.15 R54.2
NetJ1_16: J1.16 R62.1
NetJ1_17: J1.17 R55.2
NetJ1_19: J1.19 R56.2
NetJ1_21: J1.21 R57.2
NetJ1_23: J1.23 R179.2
NetJ1_25: J1.25 R180.2
NetJ1_26: J1.26 R59.1
NetJ1_27: J1.27 R181.2
NetJ1_28: J1.28 R58.1
NetJ1_29: J1.29 R182.2
NetJ1_31: J1.31 R183.2
NetJ1_33: J1.33 R184.2
NetJ1_35: J1.35 R185.2
NetJ1_37: J1.37 R186.2
NetJ1_39: J1.39 R187.2
NetJ1_41: J1.41 R188.2
NetJ1_43: J1.43 R189.2
NetJ1_44: J1.44 R53.1
NetJ1_45: J1.45 R190.2
NetJ1_46: J1.46 R52.1
NetJ1_47: J1.47 R191.2
NetJ1_49: J1.49 R192.2
NetJ1_50: J1.50 R51.1
NetJ1_51: J1.51 R23.2
NetJ1_52: J1.52 R50.1
NetJ1_53: J1.53 R22.2
NetJ1_55: J1.55 R33.2
NetJ1_56: J1.56 R49.1
NetJ1_57: J1.57 R21.2
NetJ1_58: J1.58 R48.1
NetJ1_59: J1.59 R20.2
NetJ2_1: J2.1 R111.2

Not connected (* = marked no-connect by the designer): J1 20 22 32 34 38 40

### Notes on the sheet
- HD CONNECTOR FOR LVDS/CSI AND JTAG

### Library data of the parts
J1 = CMP-0075524-1: Receptacle, 0.5 mm, 30x2, Gold, TH; Manufacturer: Samtec; Pitch_mm: 0.5; Gender: Female; Green_REACh: Passed; CT: False; Shrouded: N; RowSpacing_mm: 5.73; Green_Lifecycle: Active; Row_Count: 2
J2 = CMP-0055788-1: UMC Straight Jack Receptacle, 50 Ohm, Gold, SMT; Manufacturer: Cinch Connectivity; CNHeader: FALSE; Gender: Female
R7 R22 R23 = CMP-0027008-3: as R4 on sheet PROC011B_LP Connector
R17 R20 R27-R30 R48-R53 R58 R59 R62-R67 R69-R71 R75 R111 = CMP-0027008-3: as R144 on sheet PROC011B_PMIC
R21 R33 = CMP-0027008-3: as R8 on sheet PROC011B_LP Connector
R34 = CMP-0016044-2: as R115 on sheet PROC011B_LP Connector
R54-R57 R179-R186 R188-R192 = CMP-0078192-1: RES, 20.0, 1%, 0.05 W, 0201; Manufacturer: Vishay-Dale; Value_Code: 20R0; SizeArea_mm2: 0.18; AEC Qualified: N; AEC Category: Q200; Res_ohm: 20; Value: 20.0; SizeZ_mm: 0.33; EIA_Code: E96; TempCo: 200 ppm/C; Power_W: 50mW; VDC_V: 30V; SizeY_mm: 0.3; Value2: 0.05W; U/M: EA; SizeX_mm: 0.6
R187 = CMP-0078192-1: RES, 20.0, 1%, 0.05 W, 0201; Manufacturer: Vishay-Dale; Value_Code: 20R0; SizeArea_mm2: 0.18; AEC Qualified: N; AEC Category: Q200; Res_ohm: 20; Value: 20.0; SizeZ_mm: 0.33; EIA_Code: E96; TempCo: 200 ppm/C; Power_W: 50mW; VDC_V: 30V; SizeY_mm: 0.3; Value2: 0.05W; U/M: EA; CompType: Resistor; SizeX_mm: 0.6

## Sheet PROC011B_XDS110 Interface_1A.SchDoc: XDS110 Interface_1A
size 431 x 279 mm; Date: Not shown in title block; ApprovedBy: Not shown in title block; CheckedBy: Not shown in title block; Author: Not shown in title block; CompanyName: Not shown in title block; Engineer: Not shown in title block; Organization: Not shown in title block; Address1: Not shown in title block; Address2: Not shown in title block; Address3: Not shown in title block; Address4: Not shown in title block; DocumentNumber: 1; Revision: Use project parameter SCH_Rev; SheetNumber: 12; SheetTotal: 17; PageSetup: Record=PageOptions¦CenterHorizontal=True¦CenterVertical=True¦PrintScale=1.00¦XCorrection=1.00¦YCorrection=1.00¦PrintKind=0¦BorderSize=5000000¦LeftOffset=0¦BottomOffset=0¦Orientation=2¦PaperLength=1000¦PaperWidth=1000¦Scale=100¦PaperSource=15¦PrintQuality=600¦MediaType=1¦DitherType=10¦PaperKind=Letter¦PrintScaleMode=1

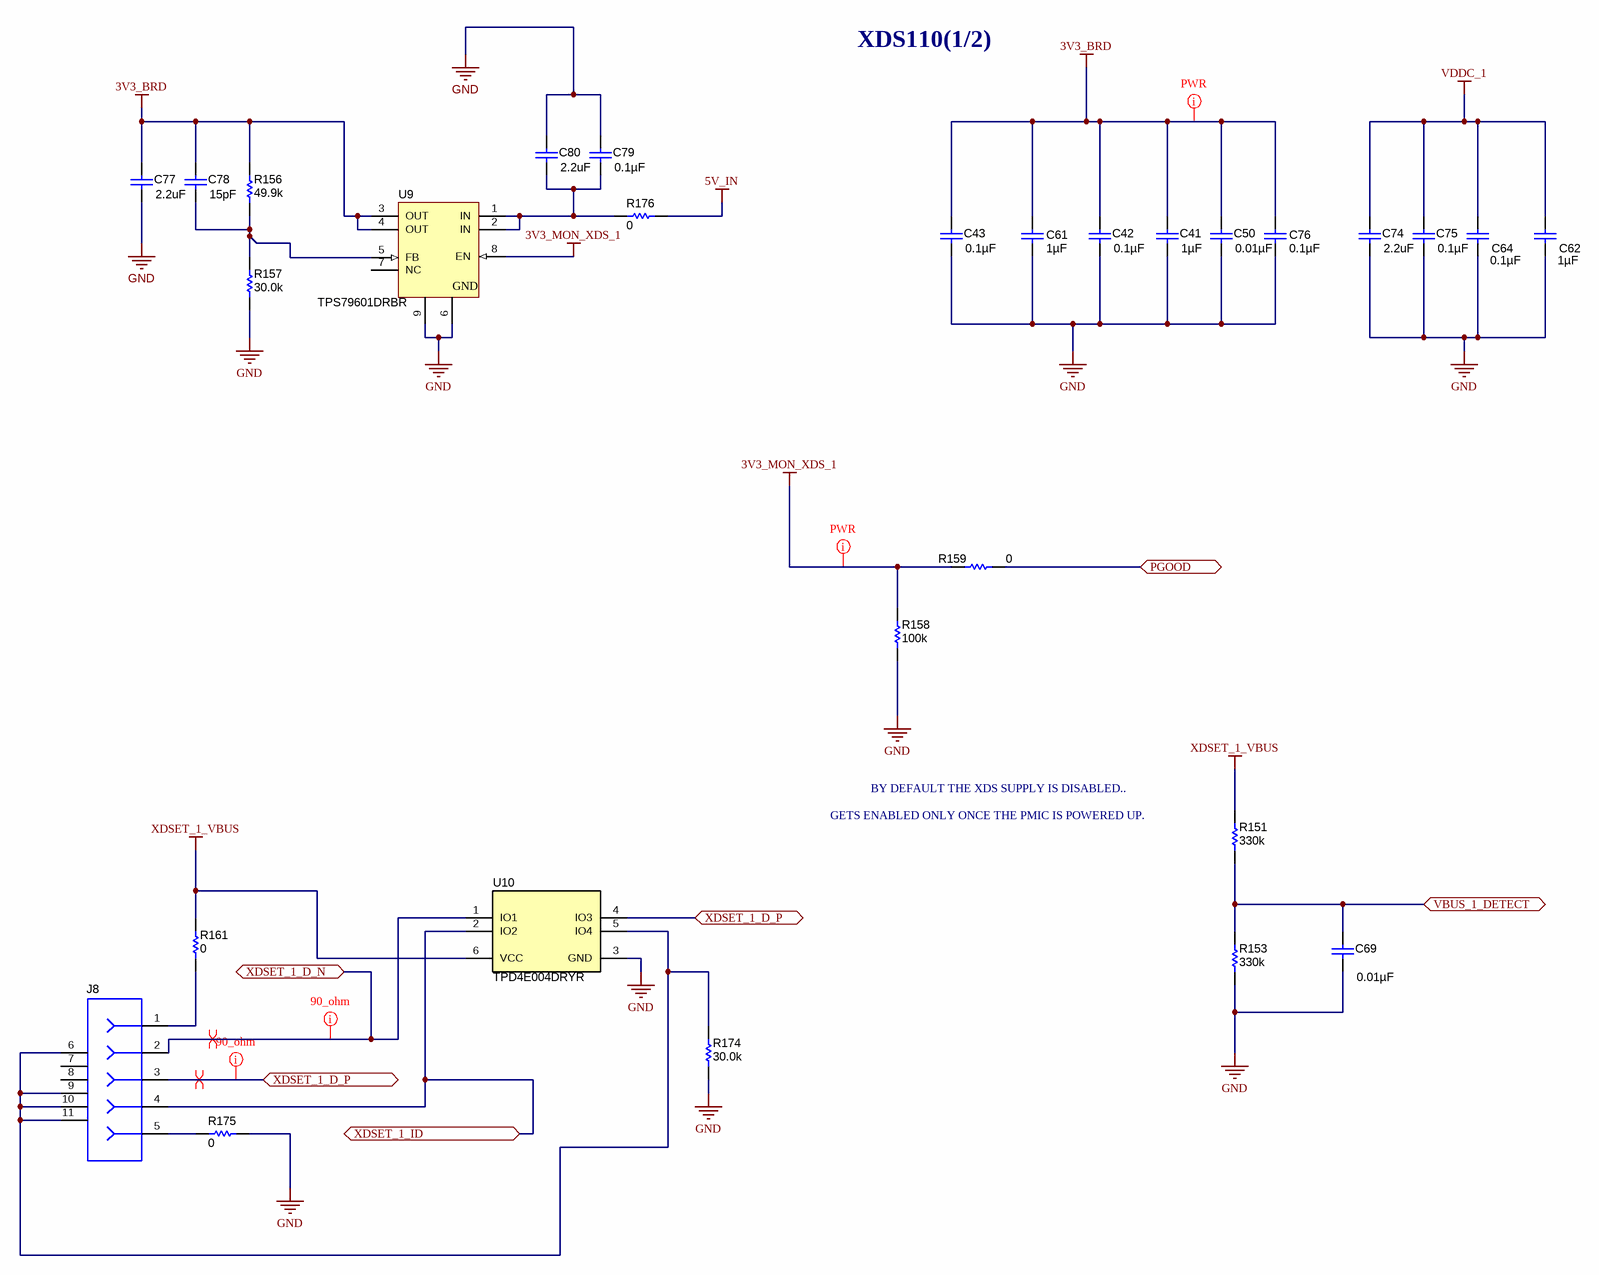
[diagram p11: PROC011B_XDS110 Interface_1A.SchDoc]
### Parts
C41  ValueDisplayed: 1µF  [0402L]  (hidden comment: C1005X7S0J105M050BC)
C42  ValueDisplayed: 0.1µF  [0402L]  (hidden comment: C0402C104K8RACTU)
C43  ValueDisplayed: 0.1µF  [0402L]  (hidden comment: C0402C104K8RACTU)
C50  ValueDisplayed: 0.01µF  [0402L]  (hidden comment: C1005X7R1E103K050BB)
C61  ValueDisplayed: 1µF  [0402L]  (hidden comment: C1005X7S0J105M050BC)
C62  ValueDisplayed: 1µF  [0402L]  (hidden comment: C1005X7S0J105M050BC)
C64  ValueDisplayed: 0.1µF  [0402L]  (hidden comment: C0402C104K8RACTU)
C69  ValueDisplayed: 0.01µF  [0402L]  (hidden comment: C0402C103K4RACTU)
C74  ValueDisplayed: 2.2uF  [0402_065L]  (hidden comment: C1005X7S1A225K050BC)
C75  ValueDisplayed: 0.1µF  [0402L]  (hidden comment: C0402C104K8RACTU)
C76  ValueDisplayed: 0.1µF  [0402L]  (hidden comment: C0402C104K8RACTU)
C77  ValueDisplayed: 2.2uF  [0402_065L]  (hidden comment: C1005X7S1A225K050BC)
C78  ValueDisplayed: 15pF  [0402L]  (hidden comment: 04025A150FAT2A)
C79  ValueDisplayed: 0.1µF  [0402L]  (hidden comment: C0402C104K8RACTU)
C80  ValueDisplayed: 2.2uF  [0402_065L]  (hidden comment: C1005X7S1A225K050BC)
J8  105017-0001  [CONN_105017-0001]  (value not drawn)
R151  ValueDisplayed: 330k  [0402L]  (hidden comment: CRCW0402330KFKED)
R153  ValueDisplayed: 330k  [0402L]  (hidden comment: CRCW0402330KFKED)
R156  ValueDisplayed: 49.9k  [0402L]  (hidden comment: CRCW040249K9FKED)
R157  ValueDisplayed: 30.0k  [0402L]  (hidden comment: CRCW040230K0FKED)
R158  ValueDisplayed: 100k  [0402L]  (hidden comment: CRCW0402100KFKED)
R159  ValueDisplayed: 0  [0402L]  (hidden comment: ERJ-2GE0R00X)
R161  ValueDisplayed: 0  [0603]  (hidden comment: MCT06030Z0000ZP500)
R174  ValueDisplayed: 30.0k  [0402L]  (hidden comment: CRCW040230K0FKED)
R175  ValueDisplayed: 0  [0603]  (hidden comment: MCT06030Z0000ZP500)
R176  ValueDisplayed: 0  [0603]  (hidden comment: MCT06030Z0000ZP500)
U9  TPS79601DRBR  [DRB0008B]
U10  TPD4E004DRYR  [DRY0006A]

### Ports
PGOOD, VBUS_1_DETECT, XDSET_1_D_N, XDSET_1_D_P, XDSET_1_ID

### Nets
3V3_BRD: C41.2 C42.2 C43.2 C50.2 C61.2 C76.2 C77.2 C78.2 R156.2 U9.3(OUT) U9.4(OUT)
3V3_MON_XDS_1: R158.2 R159.2 U9.8(EN)
5V_IN: R176.2
GND: C41.1 C42.1 C43.1 C50.1 C61.1 C62.1 C64.1 C69.1 C74.1 C75.1 C76.1 C77.1 C79.1 C80.1 R153.1 R157.1 R158.1 R174.1 R175.1 U9.6(GND) U9.9(GND) U10.3(GND)
VDDC_1: C62.2 C64.2 C74.2 C75.2
XDSET_1_VBUS: R151.2 R161.2 U10.6(VCC)
PGOOD: R159.1 ; port PGOOD
VBUS_1_DETECT: C69.2 R151.1 R153.2 ; port VBUS_1_DETECT
XDSET_1_D_N: J8.2 U10.1(IO1) ; port XDSET_1_D_N
XDSET_1_D_P: J8.3 U10.4(IO3) ; port XDSET_1_D_P
XDSET_1_ID: J8.4 U10.2(IO2) ; port XDSET_1_ID
NetC78_1: C78.1 R156.1 R157.2 U9.5(FB)
NetC79_2: C79.2 C80.2 R176.1 U9.1(IN) U9.2(IN)
NetJ8_1: J8.1 R161.1
NetJ8_5: J8.5 R175.2
NetJ8_6: J8.6 J8.9 J8.10 J8.11 R174.2 U10.5(IO4)

Not connected (* = marked no-connect by the designer): J8 7 8; U9 7(NC)

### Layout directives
net class PWR: 3V3_BRD, 3V3_MON_XDS_1
net class 90_ohm: XDSET_1_D_N, XDSET_1_D_P
differential pair: XDSET_1_D_N, XDSET_1_D_P

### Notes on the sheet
- XDS110(1/2)
- GETS ENABLED ONLY ONCE THE PMIC IS POWERED UP.
- BY DEFAULT THE XDS SUPPLY IS DISABLED..

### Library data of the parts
C41 C61 C62 = CMP-0078222-1: CAP, CERM, 1 µF, 6.3 V,+/- 20%, X7S, 0402; Manufacturer: TDK; TaMin_C: -55°C; Polarized: N; SizeAreaWB_mm2: 3; U/M: EA; Value: 1uF; TaMax_C: 125°C; SizeZ_mm: 0.6; SizeX_mm: 1; SizeY_mm: 0.5; Cap_Case: 0402; Value2: 6.3V; AEC Category: Q200
C42 C43 C64 C75 C76 C79 = CMP-0078241-1: CAP, CERM, 0.1 µF, 10 V,+/- 10%, X7R, 0402; Manufacturer: Kemet; TaMin_C: -55°C; Polarized: N; SizeAreaWB_mm2: 3; U/M: EA; Value: 0.1uF; TaMax_C: 125°C; SizeZ_mm: 0.6; SizeX_mm: 1; SizeY_mm: 0.5; Cap_Case: 0402; Value2: 10V; Cap_F: 100nF; AEC Category: Q200
C50 = CMP-0078220-1: CAP, CERM, 0.01 µF, 25 V,+/- 10%, X7R, 0402; Manufacturer: TDK; TaMin_C: -55°C; Polarized: N; Green_Lifecycle: NRND; SizeAreaWB_mm2: 3; Green_REACh: Passed; U/M: EA; Value: 0.01uF; TaMax_C: 125°C; SizeZ_mm: 0.6; SizeX_mm: 1; SizeY_mm: 0.5; Cap_Case: 0402; Value2: 25V; Cap_F: 10nF; AEC Category: Q200
C69 = CMP-0078218-1: CAP, CERM, 0.01 µF, 16 V,+/- 10%, X7R, 0402; Manufacturer: Kemet; TaMin_C: -55°C; Polarized: N; Green_Lifecycle: Active; SizeAreaWB_mm2: 3; Green_REACh: Passed; U/M: EA; Value: 0.01uF; TaMax_C: 125°C; SizeZ_mm: 0.6; SizeX_mm: 1; SizeY_mm: 0.5; Cap_Case: 0402; Value2: 16V; Cap_F: 10nF; AEC Category: Q200
C74 C77 C80 = CMP-0006302-2: CAP, CERM, 2.2 uF, 10 V, +/- 10%, X7S, 0402; Manufacturer: TDK; TaMin_C: -55°C; ESR_ohm: 5.925m; Polarized: N; SizeAreaWB_mm2: 3; Value1: 0.005925 ohm; U/M: EA; Value: 2.2uF; TaMax_C: 125°C; SizeZ_mm: 0.65; SizeX_mm: 1; SizeY_mm: 0.5; Cap_Case: 0402_065; Value2: 10V; CompType: Capacitor; Cap_F: 2.2µF; IRMS_A: 2.05591A; AEC Category: Q200
C78 = CMP-0078217-1: CAP, CERM, 15 pF, 50 V,+/- 1%, C0G/NP0, 0402; Manufacturer: AVX; TaMin_C: -55°C; Polarized: N; Green_Lifecycle: Not Set; SizeAreaWB_mm2: 3; Green_REACh: Incomplete; U/M: EA; Value: 15pF; TaMax_C: 125°C; SizeZ_mm: 0.6; SizeX_mm: 1; SizeY_mm: 0.5; Cap_Case: 0402; Value2: 50V; AEC Category: Q200
J8 = CMP-0055293-1: Connector, Receptacle, Micro-USB Type B, R/A, Bottom Mount SMT; Manufacturer: Molex; CNHeader: FALSE; Green_Lifecycle: Active; Gender: Female; Green_REACh: Passed; CompType: USB; CT: TRUE
R151 R153 = CMP-0078210-1: RES, 330 k, 1%, 0.063 W, AEC-Q200 Grade 0, 0402; Manufacturer: Vishay-Dale; SizeArea_mm2: 0.5; AEC Qualified: Y; AEC Category: Q200; Value: 330k; SizeZ_mm: 0.6; TempCo: 100 ppm/C; AEC Grade: 0; Power_W: 63mW; VDC_V: 50V; Value2: 0.063W; U/M: EA; SizeX_mm: 1
R156 = CMP-0026403-1: RES, 49.9 k, 1%, 0.063 W, 0402; Manufacturer: Vishay-Dale; Power_W: 63mW; TempCo: 100 ppm/C; Value_Code: 49k9; U/M: EA; Value: 49.9k; EIA_Code: E96; SizeX_mm: 1; SizeY_mm: 0.5; SizeZ_mm: 0.6; Value2: 0.063W; VDC_V: 50V; AEC Category: Q200
R157 R174 = CMP-0078244-1: RES, 30.0 k, 1%, 0.063 W, AEC-Q200 Grade 0, 0402; Manufacturer: Vishay-Dale; Power_W: 63mW; Green_Lifecycle: Active; TempCo: 100 ppm/C; Value_Code: 30k0; Green_REACh: Passed; Value: 30.0k; Res_ohm: 30k; SizeX_mm: 1; SizeY_mm: 0.5; SizeZ_mm: 0.6; Value2: 0.063W; AEC Qualified: Y; VDC_V: 50V; AEC Grade: 0; AEC Category: Q200
R158 = CMP-0025950-2: as R138 on sheet PROC011B_PMIC
R159 = CMP-0026992-2: as R141 on sheet PROC011B_PMIC
R161 R175 R176 = CMP-0025884-3: RES, 0, 5%, 0.125 W, 0603; Manufacturer: Vishay/Beyschlag; Power_W: 125mW; TempCo: ppm/C; Value_Code: 0000; U/M: EA; Value: 0; EIA_Code: E24; SizeX_mm: 1.6; SizeY_mm: 0.8; SizeZ_mm: 1; Value2: 0.125W; SizeArea_mm2: 1.28; AEC Qualified: N; AEC Category: Q200
U9 = CMP-0036402-2: Single Output High PSRR LDO, 1 A, Adjustable 1.2 to 5.5 V Output, 2.7 to 5.5 V Input, 8-pin SON (DRB), -40 to 125 degC, Green (RoHS & no Sb/Br); Manufacturer: Texas Instruments; Vin(Min)(V): 2.7; Vout Adj(Max)(V): 5.5; Vout Adj(Min)(V): 1.2; Accuracy(%): 2; SubFamily: Single Channel LDO; Iq(Typ)(mA): 0.26; Vdo(Typ)(mV): 250; Iout(Max)(A): 1
U10 = CMP-0043115-1: ESD-Protection Array for High-Speed Data Interfaces, 4 Channels, -40 to +85 degC, 6-pin SON (DRY), Green (RoHS & no Sb/Br); Manufacturer: Texas Instruments; IO Leakage Current(nA): 1; USB High Speed: TRUE; IO Capacitance(Typ)(pF): 1.6; SubFamily: ESD Solution; IEC 61000-4-2 Contact(+/- kV): 8; Breakdown Voltage(Min)(V): 6; IEC 61000-4-2 Air-Gap(+/- kV): 12

## Sheet PROC011B_XDS110 Interface_1B.SchDoc: XDS110 Interface_1B
size 431 x 279 mm; Date: Not shown in title block; ApprovedBy: Not shown in title block; CheckedBy: Not shown in title block; Author: Not shown in title block; CompanyName: Not shown in title block; Engineer: Not shown in title block; Organization: Not shown in title block; Address1: Not shown in title block; Address2: Not shown in title block; Address3: Not shown in title block; Address4: Not shown in title block; DocumentNumber: 1; Revision: Use project parameter SCH_Rev; SheetNumber: 13; SheetTotal: 17; PageSetup: Record=PageOptions¦CenterHorizontal=True¦CenterVertical=True¦PrintScale=1.00¦XCorrection=1.00¦YCorrection=1.00¦PrintKind=0¦BorderSize=5000000¦LeftOffset=0¦BottomOffset=0¦Orientation=2¦PaperLength=1000¦PaperWidth=1000¦Scale=100¦PaperSource=15¦PrintQuality=600¦MediaType=1¦DitherType=10¦PaperKind=Letter¦PrintScaleMode=1

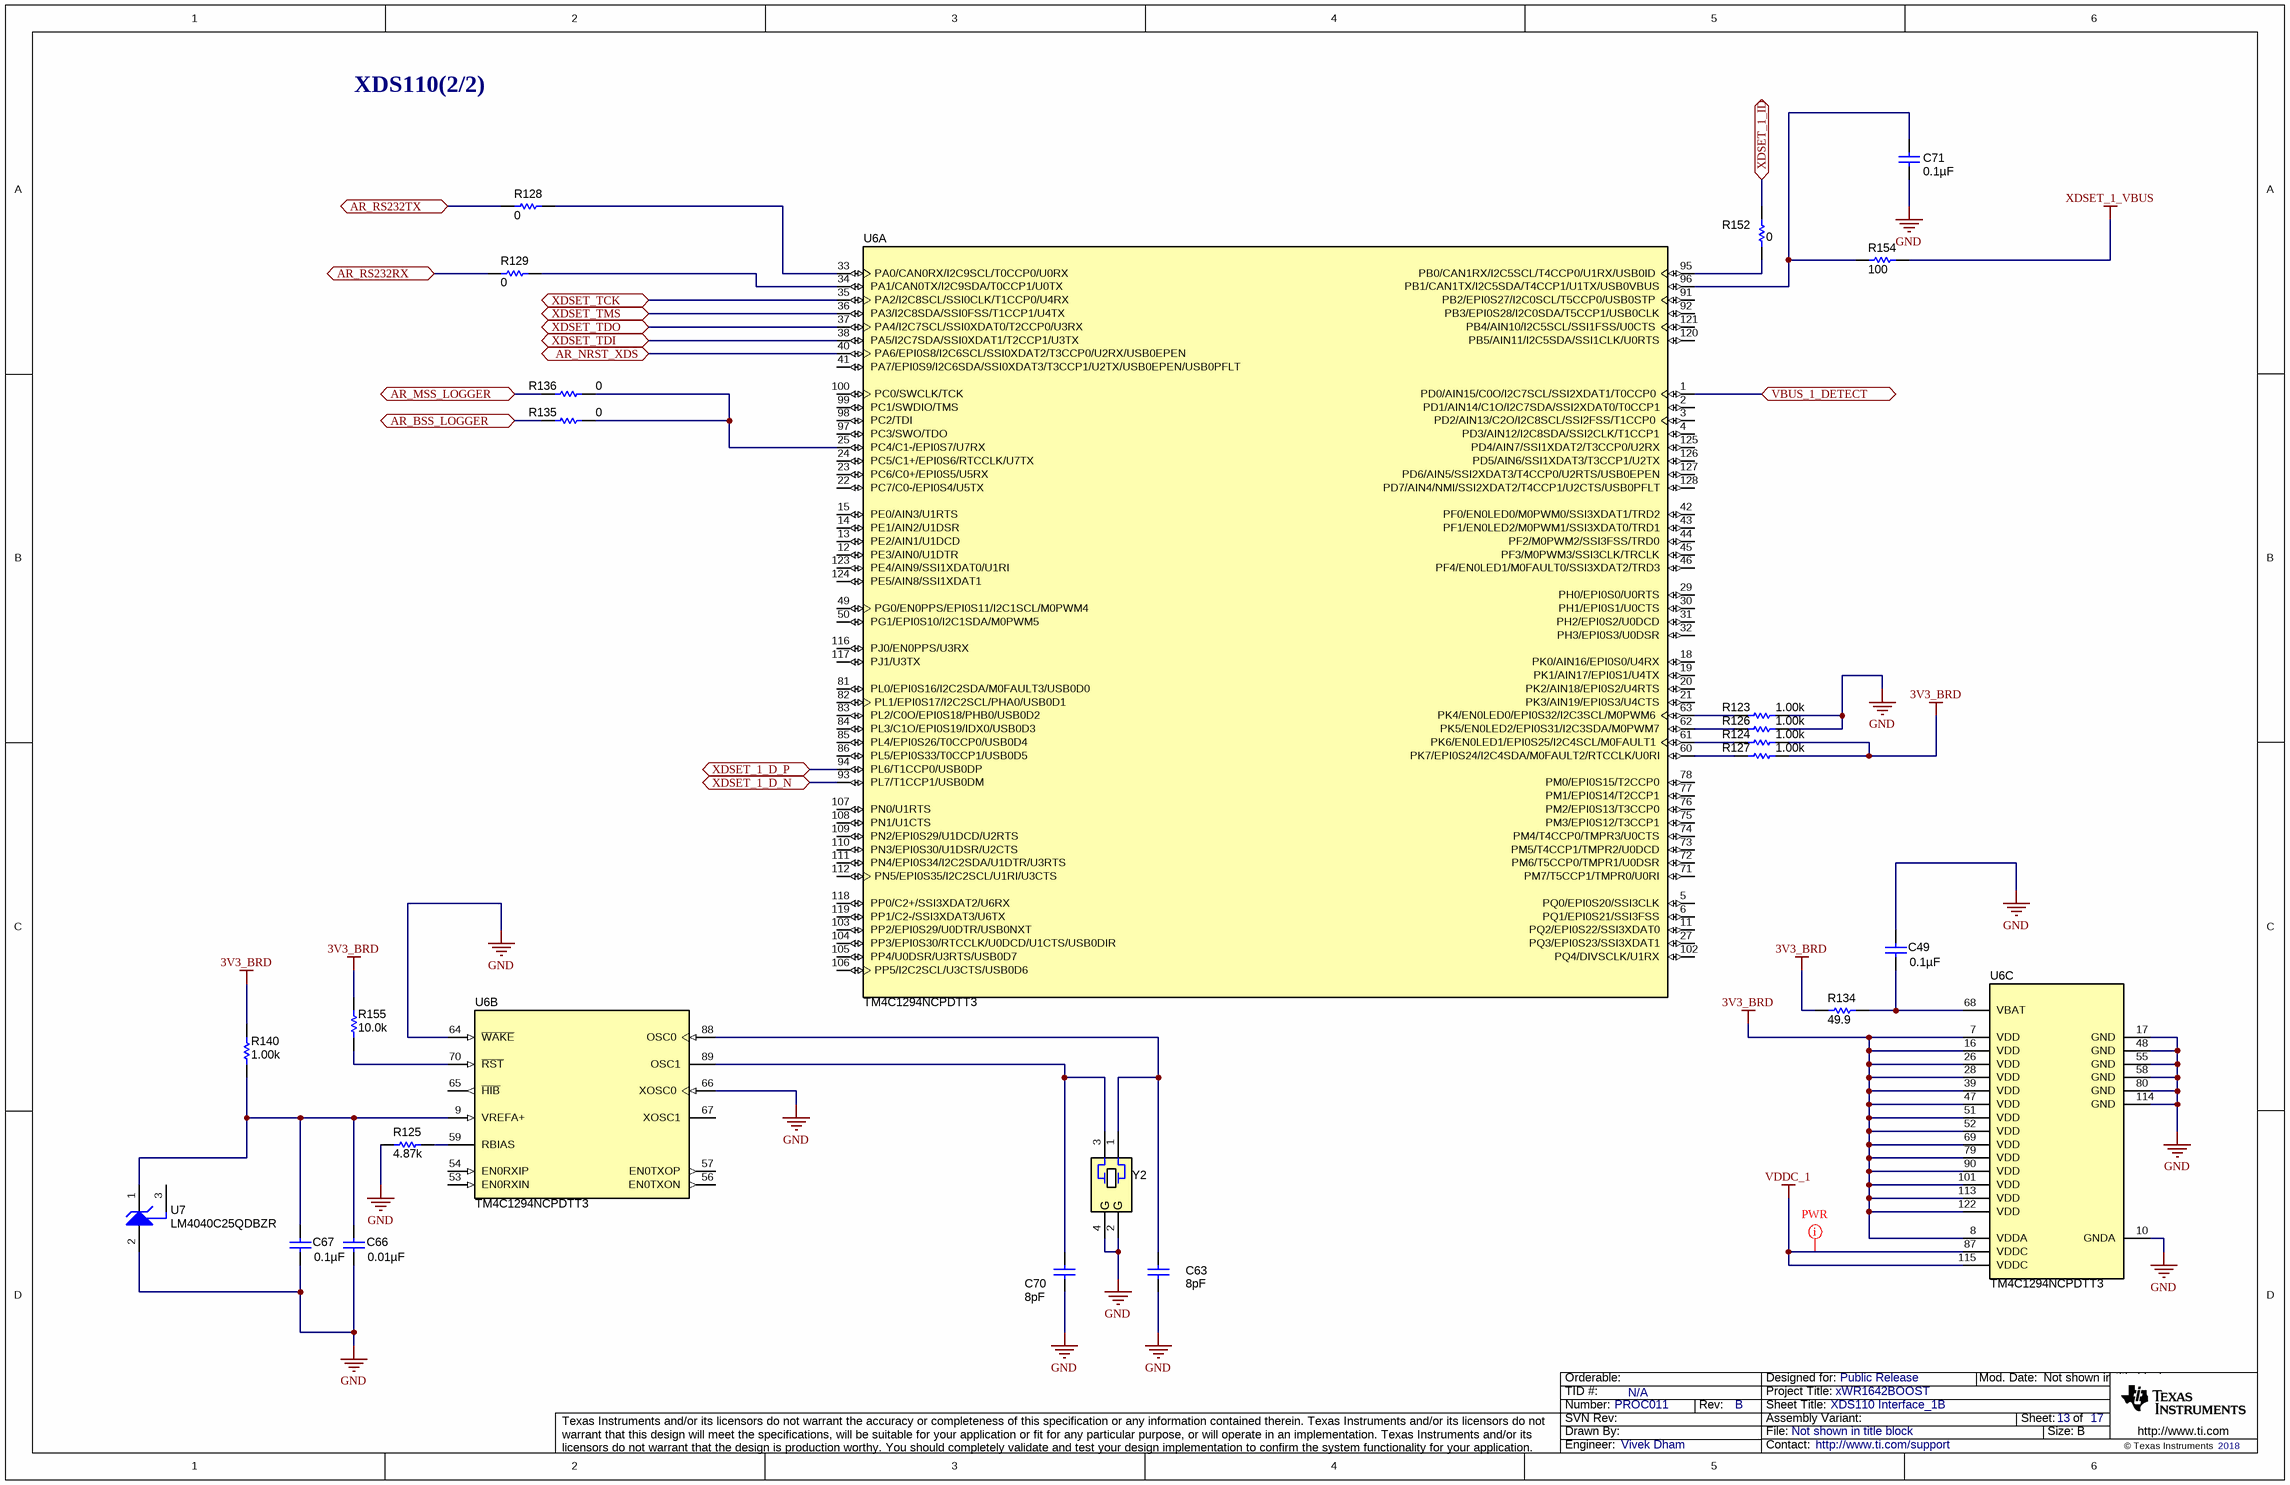
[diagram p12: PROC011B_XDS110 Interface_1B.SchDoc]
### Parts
C49  ValueDisplayed: 0.1µF  [0402L]  (hidden comment: C0402C104K8RACTU)
C63  ValueDisplayed: 8pF  [0402L]  (hidden comment: GRM1555C1H8R0DA01D)
C66  ValueDisplayed: 0.01µF  [0402L]  (hidden comment: C0402C103K4RACTU)
C67  ValueDisplayed: 0.1µF  [0402L]  (hidden comment: C0402C104K8RACTU)
C70  ValueDisplayed: 8pF  [0402L]  (hidden comment: GRM1555C1H8R0DA01D)
C71  ValueDisplayed: 0.1µF  [0402L]  (hidden comment: C0402C104K8RACTU)
R123  ValueDisplayed: 1.00k  [0402L]  (hidden comment: CRCW04021K00FKED)
R124  ValueDisplayed: 1.00k  [0402L]  (hidden comment: CRCW04021K00FKED)
R125  ValueDisplayed: 4.87k  [0402L]  (hidden comment: CRCW04024K87FKED)
R126  ValueDisplayed: 1.00k  [0402L]  (hidden comment: CRCW04021K00FKED)
R127  ValueDisplayed: 1.00k  [0402L]  (hidden comment: CRCW04021K00FKED)
R128  ValueDisplayed: 0  [0402L]  (hidden comment: ERJ-2GE0R00X)
R129  ValueDisplayed: 0  [0402L]  (hidden comment: ERJ-2GE0R00X)
R134  ValueDisplayed: 49.9  [0402L]  (hidden comment: CRCW040249R9FKED)
R135  ValueDisplayed: 0  [0201_Silk]  (hidden comment: CRCW02010000Z0ED)
R136  ValueDisplayed: 0  [0201_Silk]  (hidden comment: CRCW02010000Z0ED)
R140  ValueDisplayed: 1.00k  [0402L]  (hidden comment: CRCW04021K00FKED)
R152  ValueDisplayed: 0  [0402L]  (hidden comment: ERJ-2GE0R00X)
R154  ValueDisplayed: 100  [0402L]  (hidden comment: ERJ-2GEJ101X)
R155  ValueDisplayed: 10.0k  [0402L]  (hidden comment: CRCW040210K0FKED)
U6  TM4C1294NCPDTT3  [PDT0128A]  (parts A,B,C of 3)
U7  LM4040C25QDBZR  [DBZ0003A_N]
Y2  NX3225SA-16.000M-STD-CRS-2  [NDK_NX3225SA]  (value not drawn)

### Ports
AR_BSS_LOGGER, AR_MSS_LOGGER, AR_NRST_XDS, AR_RS232RX, AR_RS232TX, VBUS_1_DETECT, XDSET_1_D_N, XDSET_1_D_P, XDSET_1_ID, XDSET_TCK, XDSET_TDI, XDSET_TDO, XDSET_TMS

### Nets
3V3_BRD: R124.2 R127.2 R134.2 R140.2 R155.2 U6.7(VDD) U6.8(VDDA) U6.16(VDD) U6.26(VDD) U6.28(VDD) U6.39(VDD) U6.47(VDD) U6.51(VDD) U6.52(VDD) U6.69(VDD) U6.79(VDD) U6.90(VDD) U6.101(VDD) U6.113(VDD) U6.122(VDD)
GND: C49.1 C63.1 C66.1 C67.1 C70.1 C71.1 R123.2 R125.1 R126.2 U6.10(GNDA) U6.17(GND) U6.48(GND) U6.55(GND) U6.58(GND) U6.64(~{WAKE}) U6.66(XOSC0) U6.80(GND) U6.114(GND) U7.2(ANODE) Y2.2(GND) Y2.4(GND)
VDDC_1: U6.87(VDDC) U6.115(VDDC)
XDSET_1_VBUS: R154.2
AR_BSS_LOGGER: R135.1 ; port AR_BSS_LOGGER
AR_MSS_LOGGER: R136.1 ; port AR_MSS_LOGGER
AR_NRST_XDS: U6.40(PA6/EPI0S8/I2C6SCL/SSI0XDAT2/T3CCP0/U2RX/USB0EPEN) ; port AR_NRST_XDS
AR_RS232RX: R129.1 ; port AR_RS232RX
AR_RS232TX: R128.1 ; port AR_RS232TX
VBUS_1_DETECT: U6.1(PD0/AIN15/C0O/I2C7SCL/SSI2XDAT1/T0CCP0) ; port VBUS_1_DETECT
XDSET_1_D_N: U6.93(PL7/T1CCP1/USB0DM) ; port XDSET_1_D_N
XDSET_1_D_P: U6.94(PL6/T1CCP0/USB0DP) ; port XDSET_1_D_P
XDSET_1_ID: R152.2 ; port XDSET_1_ID
XDSET_TCK: U6.35(PA2/I2C8SCL/SSI0CLK/T1CCP0/U4RX) ; port XDSET_TCK
XDSET_TDI: U6.38(PA5/I2C7SDA/SSI0XDAT1/T2CCP1/U3TX) ; port XDSET_TDI
XDSET_TDO: U6.37(PA4/I2C7SCL/SSI0XDAT0/T2CCP0/U3RX) ; port XDSET_TDO
XDSET_TMS: U6.36(PA3/I2C8SDA/SSI0FSS/T1CCP1/U4TX) ; port XDSET_TMS
NetC49_2: C49.2 R134.1 U6.68(VBAT)
NetC63_2: C63.2 U6.88(OSC0) Y2.1
NetC66_2: C66.2 C67.2 R140.1 U6.9(VREFA+) U7.1(CATHODE)
NetC70_2: C70.2 U6.89(OSC1) Y2.3
NetC71_2: C71.2 R154.1 U6.96(PB1/CAN1TX/I2C5SDA/T4CCP1/U1TX/USB0VBUS)
NetR123_1: R123.1 U6.63(PK4/EN0LED0/EPI0S32/I2C3SCL/M0PWM6)
NetR124_1: R124.1 U6.61(PK6/EN0LED1/EPI0S25/I2C4SCL/M0FAULT1)
NetR125_2: R125.2 U6.59(RBIAS)
NetR126_1: R126.1 U6.62(PK5/EN0LED2/EPI0S31/I2C3SDA/M0PWM7)
NetR127_1: R127.1 U6.60(PK7/EPI0S24/I2C4SDA/M0FAULT2/RTCCLK/U0RI)
NetR128_2: R128.2 U6.33(PA0/CAN0RX/I2C9SCL/T0CCP0/U0RX)
NetR129_2: R129.2 U6.34(PA1/CAN0TX/I2C9SDA/T0CCP1/U0TX)
NetR135_2: R135.2 R136.2 U6.25(PC4/C1-/EPI0S7/U7RX)
NetR152_1: R152.1 U6.95(PB0/CAN1RX/I2C5SCL/T4CCP0/U1RX/USB0ID)
NetR155_1: R155.1 U6.70(~{RST})

Not connected (* = marked no-connect by the designer): U6 2(PD1/AIN14/C1O/I2C7SDA/SSI2XDAT0/T0CCP1) 3(PD2/AIN13/C2O/I2C8SCL/SSI2FSS/T1CCP0) 4(PD3/AIN12/I2C8SDA/SSI2CLK/T1CCP1) 5(PQ0/EPI0S20/SSI3CLK) 6(PQ1/EPI0S21/SSI3FSS) 11(PQ2/EPI0S22/SSI3XDAT0) 12(PE3/AIN0/U1DTR) 13(PE2/AIN1/U1DCD) 14(PE1/AIN2/U1DSR) 15(PE0/AIN3/U1RTS) 18(PK0/AIN16/EPI0S0/U4RX) 19(PK1/AIN17/EPI0S1/U4TX) 20(PK2/AIN18/EPI0S2/U4RTS) 21(PK3/AIN19/EPI0S3/U4CTS) 22(PC7/C0-/EPI0S4/U5TX) 23(PC6/C0+/EPI0S5/U5RX) 24(PC5/C1+/EPI0S6/RTCCLK/U7TX) 27(PQ3/EPI0S23/SSI3XDAT1) 29(PH0/EPI0S0/U0RTS) 30(PH1/EPI0S1/U0CTS) 31(PH2/EPI0S2/U0DCD) 32(PH3/EPI0S3/U0DSR) 41(PA7/EPI0S9/I2C6SDA/SSI0XDAT3/T3CCP1/U2TX/USB0EPEN/USB0PFLT) 42(PF0/EN0LED0/M0PWM0/SSI3XDAT1/TRD2) 43(PF1/EN0LED2/M0PWM1/SSI3XDAT0/TRD1) 44(PF2/M0PWM2/SSI3FSS/TRD0) 45(PF3/M0PWM3/SSI3CLK/TRCLK) 46(PF4/EN0LED1/M0FAULT0/SSI3XDAT2/TRD3) 49(PG0/EN0PPS/EPI0S11/I2C1SCL/M0PWM4) 50(PG1/EPI0S10/I2C1SDA/M0PWM5) 53(EN0RXIN) 54(EN0RXIP) 56(EN0TXON) 57(EN0TXOP) 65(~{HIB}) 67(XOSC1) 71(PM7/T5CCP1/TMPR0/U0RI) 72(PM6/T5CCP0/TMPR1/U0DSR) 73(PM5/T4CCP1/TMPR2/U0DCD) 74(PM4/T4CCP0/TMPR3/U0CTS) 75(PM3/EPI0S12/T3CCP1) 76(PM2/EPI0S13/T3CCP0) 77(PM1/EPI0S14/T2CCP1) 78(PM0/EPI0S15/T2CCP0) 81(PL0/EPI0S16/I2C2SDA/M0FAULT3/USB0D0) 82(PL1/EPI0S17/I2C2SCL/PHA0/USB0D1) 83(PL2/C0O/EPI0S18/PHB0/USB0D2) 84(PL3/C1O/EPI0S19/IDX0/USB0D3) 85(PL4/EPI0S26/T0CCP0/USB0D4) 86(PL5/EPI0S33/T0CCP1/USB0D5) 91(PB2/EPI0S27/I2C0SCL/T5CCP0/USB0STP) 92(PB3/EPI0S28/I2C0SDA/T5CCP1/USB0CLK) 97(PC3/SWO/TDO) 98(PC2/TDI) 99(PC1/SWDIO/TMS) 100(PC0/SWCLK/TCK) 102(PQ4/DIVSCLK/U1RX) 103(PP2/EPI0S29/U0DTR/USB0NXT) 104(PP3/EPI0S30/RTCCLK/U0DCD/U1CTS/USB0DIR) 105(PP4/U0DSR/U3RTS/USB0D7) 106(PP5/I2C2SCL/U3CTS/USB0D6) 107(PN0/U1RTS) 108(PN1/U1CTS) 109(PN2/EPI0S29/U1DCD/U2RTS) 110(PN3/EPI0S30/U1DSR/U2CTS) 111(PN4/EPI0S34/I2C2SDA/U1DTR/U3RTS) 112(PN5/EPI0S35/I2C2SCL/U1RI/U3CTS) 116(PJ0/EN0PPS/U3RX) 117(PJ1/U3TX) 118(PP0/C2+/SSI3XDAT2/U6RX) 119(PP1/C2-/SSI3XDAT3/U6TX) 120(PB5/AIN11/I2C5SDA/SSI1CLK/U0RTS) 121(PB4/AIN10/I2C5SCL/SSI1FSS/U0CTS) 123(PE4/AIN9/SSI1XDAT0/U1RI) 124(PE5/AIN8/SSI1XDAT1) 125(PD4/AIN7/SSI1XDAT2/T3CCP0/U2RX) 126(PD5/AIN6/SSI1XDAT3/T3CCP1/U2TX) 127(PD6/AIN5/SSI2XDAT3/T4CCP0/U2RTS/USB0EPEN) 128(PD7/AIN4/NMI/SSI2XDAT2/T4CCP1/U2CTS/USB0PFLT); U7 3(NC)

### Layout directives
net class PWR: VDDC_1

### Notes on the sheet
- XDS110(2/2)

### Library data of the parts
C49 = CMP-0078241-1: CAP, CERM, 0.1 µF, 10 V,+/- 10%, X7R, 0402; Manufacturer: Kemet; TaMin_C: -55°C; Polarized: N; SizeAreaWB_mm2: 3; U/M: EA; Value: 0.1uF; TaMax_C: 125°C; SizeZ_mm: 0.6; SizeX_mm: 1; SizeY_mm: 0.5; Cap_Case: 0402; Value2: 10V; CompType: Capacitor; Cap_F: 100nF; AEC Category: Q200
C63 C70 = CMP-0006494-2: CAP, CERM, 8 pF, 50 V, +/- 6%, C0G/NP0, 0402; Manufacturer: MuRata; TaMin_C: -55°C; Polarized: N; SizeAreaWB_mm2: 3; Value1: Unknown; U/M: EA; Value: 8pF; TaMax_C: 125°C; SizeZ_mm: 0.6; SizeX_mm: 1; SizeY_mm: 0.5; Cap_Case: 0402; Value2: 50V; CompType: Capacitor; AEC Category: Q200
C66 = CMP-0078218-1: as C69 on sheet PROC011B_XDS110 Interface_1A
C67 C71 = CMP-0078241-1: as C42 on sheet PROC011B_XDS110 Interface_1A
R123 R124 R126 R127 R140 = CMP-0026071-2: RES, 1.00 k, 1%, 0.063 W, 0402; Manufacturer: Vishay-Dale; Power_W: 63mW; TempCo: 100 ppm/C; Value_Code: 1k00; U/M: EA; Value: 1.00k; EIA_Code: E96; Res_ohm: 1k; SizeX_mm: 1; SizeY_mm: 0.5; SizeZ_mm: 0.6; Value2: 0.063W; VDC_V: 50V; AEC Category: Q200
R125 = CMP-0026413-1: RES, 4.87 k, 1%, 0.063 W, 0402; Manufacturer: Vishay-Dale; Power_W: 63mW; TempCo: 100 ppm/C; Value_Code: 4k87; U/M: EA; Value: 4.87k; EIA_Code: E96; SizeX_mm: 1; SizeY_mm: 0.5; SizeZ_mm: 0.6; Value2: 0.063W; VDC_V: 50V; AEC Category: Q200
R128 R129 R152 = CMP-0026992-2: as R141 on sheet PROC011B_PMIC
R134 = CMP-0026404-1: RES, 49.9, 1%, 0.063 W, 0402; Manufacturer: Vishay-Dale; Power_W: 63mW; TempCo: 100 ppm/C; Value_Code: 49R9; U/M: EA; Value: 49.9; EIA_Code: E96; SizeX_mm: 1; SizeY_mm: 0.5; SizeZ_mm: 0.6; Value2: 0.063W; VDC_V: 50V; AEC Category: Q200
R135 = CMP-0027008-3: RES, 0, 5%, 0.05 W, 0201; Manufacturer: Vishay-Dale; Power_W: 50mW; TempCo: ppm/C; Value_Code: 0000; U/M: EA; Value: 0; EIA_Code: E24; SizeX_mm: 0.6; SizeY_mm: 0.3; SizeZ_mm: 0.26; Value2: 0.05W; SizeArea_mm2: 0.18; AEC Qualified: N; AEC Category: Q200; INSTALATION: DNP
R136 = CMP-0027008-3: as R144 on sheet PROC011B_PMIC
R154 = CMP-0026993-2: RES, 100, 5%, 0.1 W, AEC-Q200 Grade 0, 0402; Manufacturer: Panasonic; Power_W: 100mW; TempCo: 200 ppm/C; Value_Code: 100R; U/M: EA; Value: 100; EIA_Code: E24; SizeX_mm: 1; SizeY_mm: 0.5; SizeZ_mm: 0.6; Value2: 0.1W; AEC Qualified: Y; AEC Grade: 0; AEC Category: Q200
R155 = CMP-0025958-2: as R145 on sheet PROC011B_PMIC
U6 = CMP-0029856-2: Tiva C Series Microcontroller, 1024 KB Flash, 256 KB SRAM, 12 Bit, 20 Channels, -40 to 105 degC, 128-Pin TQFP (PDT), Green (RoHS & no Sb/Br), Tray; Manufacturer: Texas Instruments; ADC Channels: 20; CPU: ARM Cortex-M4; Flash: 1024 KB; ADC Resolution: 12 Bits; Max Speed: 120 MHz; SRAM: 256 KB; SizeAreaWB_mm2: 324.0; SizeArea_mm2: 256.0; SizeX_mm: 16.0; SizeZ_mm: 1.2; CompType: IC
U7 = CMP-0033001-1: Precision Micropower Shunt Voltage Reference, 0.5% accuracy, 2.5 V, 15 ppm / degC, 15 mA, -40 to 125 degC, 3-pin SOT-23 (DBZ), Green (RoHS & no Sb/Br); Manufacturer: Texas Instruments; Initial Accuracy @ 25/deg C(%): 0.5; Temp Coeff(Typ)(ppm/ degree C): 15; Temp Coeff(Max)(ppm/ degree C): 100; Rating: Catalog; Min Iz for Regulation(uA): 75; VO(V): 2.5
Y2 = CMP-0078214-2: Crystal, 16 MHz, 15 ppm, 8 pF, AEC-Q200 Grade 1, SMD; Manufacturer: NDK; TaMin_C: -40°C; Frequency Tolerance: 10 ppm; Frequency Stability: 150 ppm; Load Capacitance: 7.36 pF; Frequency_Fixed: 16MHz; TaMax_C: 125°C; AEC Qualified: N; AEC Grade: 1; AEC Category: Q200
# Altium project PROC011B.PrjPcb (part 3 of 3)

## Sheet PROC011B_CAN Interface.SchDoc: CAN Interface
size 431 x 279 mm; Date: Not shown in title block; ApprovedBy: Not shown in title block; CheckedBy: Not shown in title block; Author: Not shown in title block; CompanyName: Not shown in title block; Engineer: Not shown in title block; Organization: Not shown in title block; Address1: Not shown in title block; Address2: Not shown in title block; Address3: Not shown in title block; Address4: Not shown in title block; DocumentNumber: 1; Revision: Use project parameter SCH_Rev; SheetNumber: 14; SheetTotal: 17; PageSetup: Record=PageOptions¦CenterHorizontal=True¦CenterVertical=True¦PrintScale=1.00¦XCorrection=1.00¦YCorrection=1.00¦PrintKind=0¦BorderSize=5000000¦LeftOffset=0¦BottomOffset=0¦Orientation=2¦PaperLength=1000¦PaperWidth=1000¦Scale=100¦PaperSource=15¦PrintQuality=600¦MediaType=1¦DitherType=10¦PaperKind=Letter¦PrintScaleMode=1

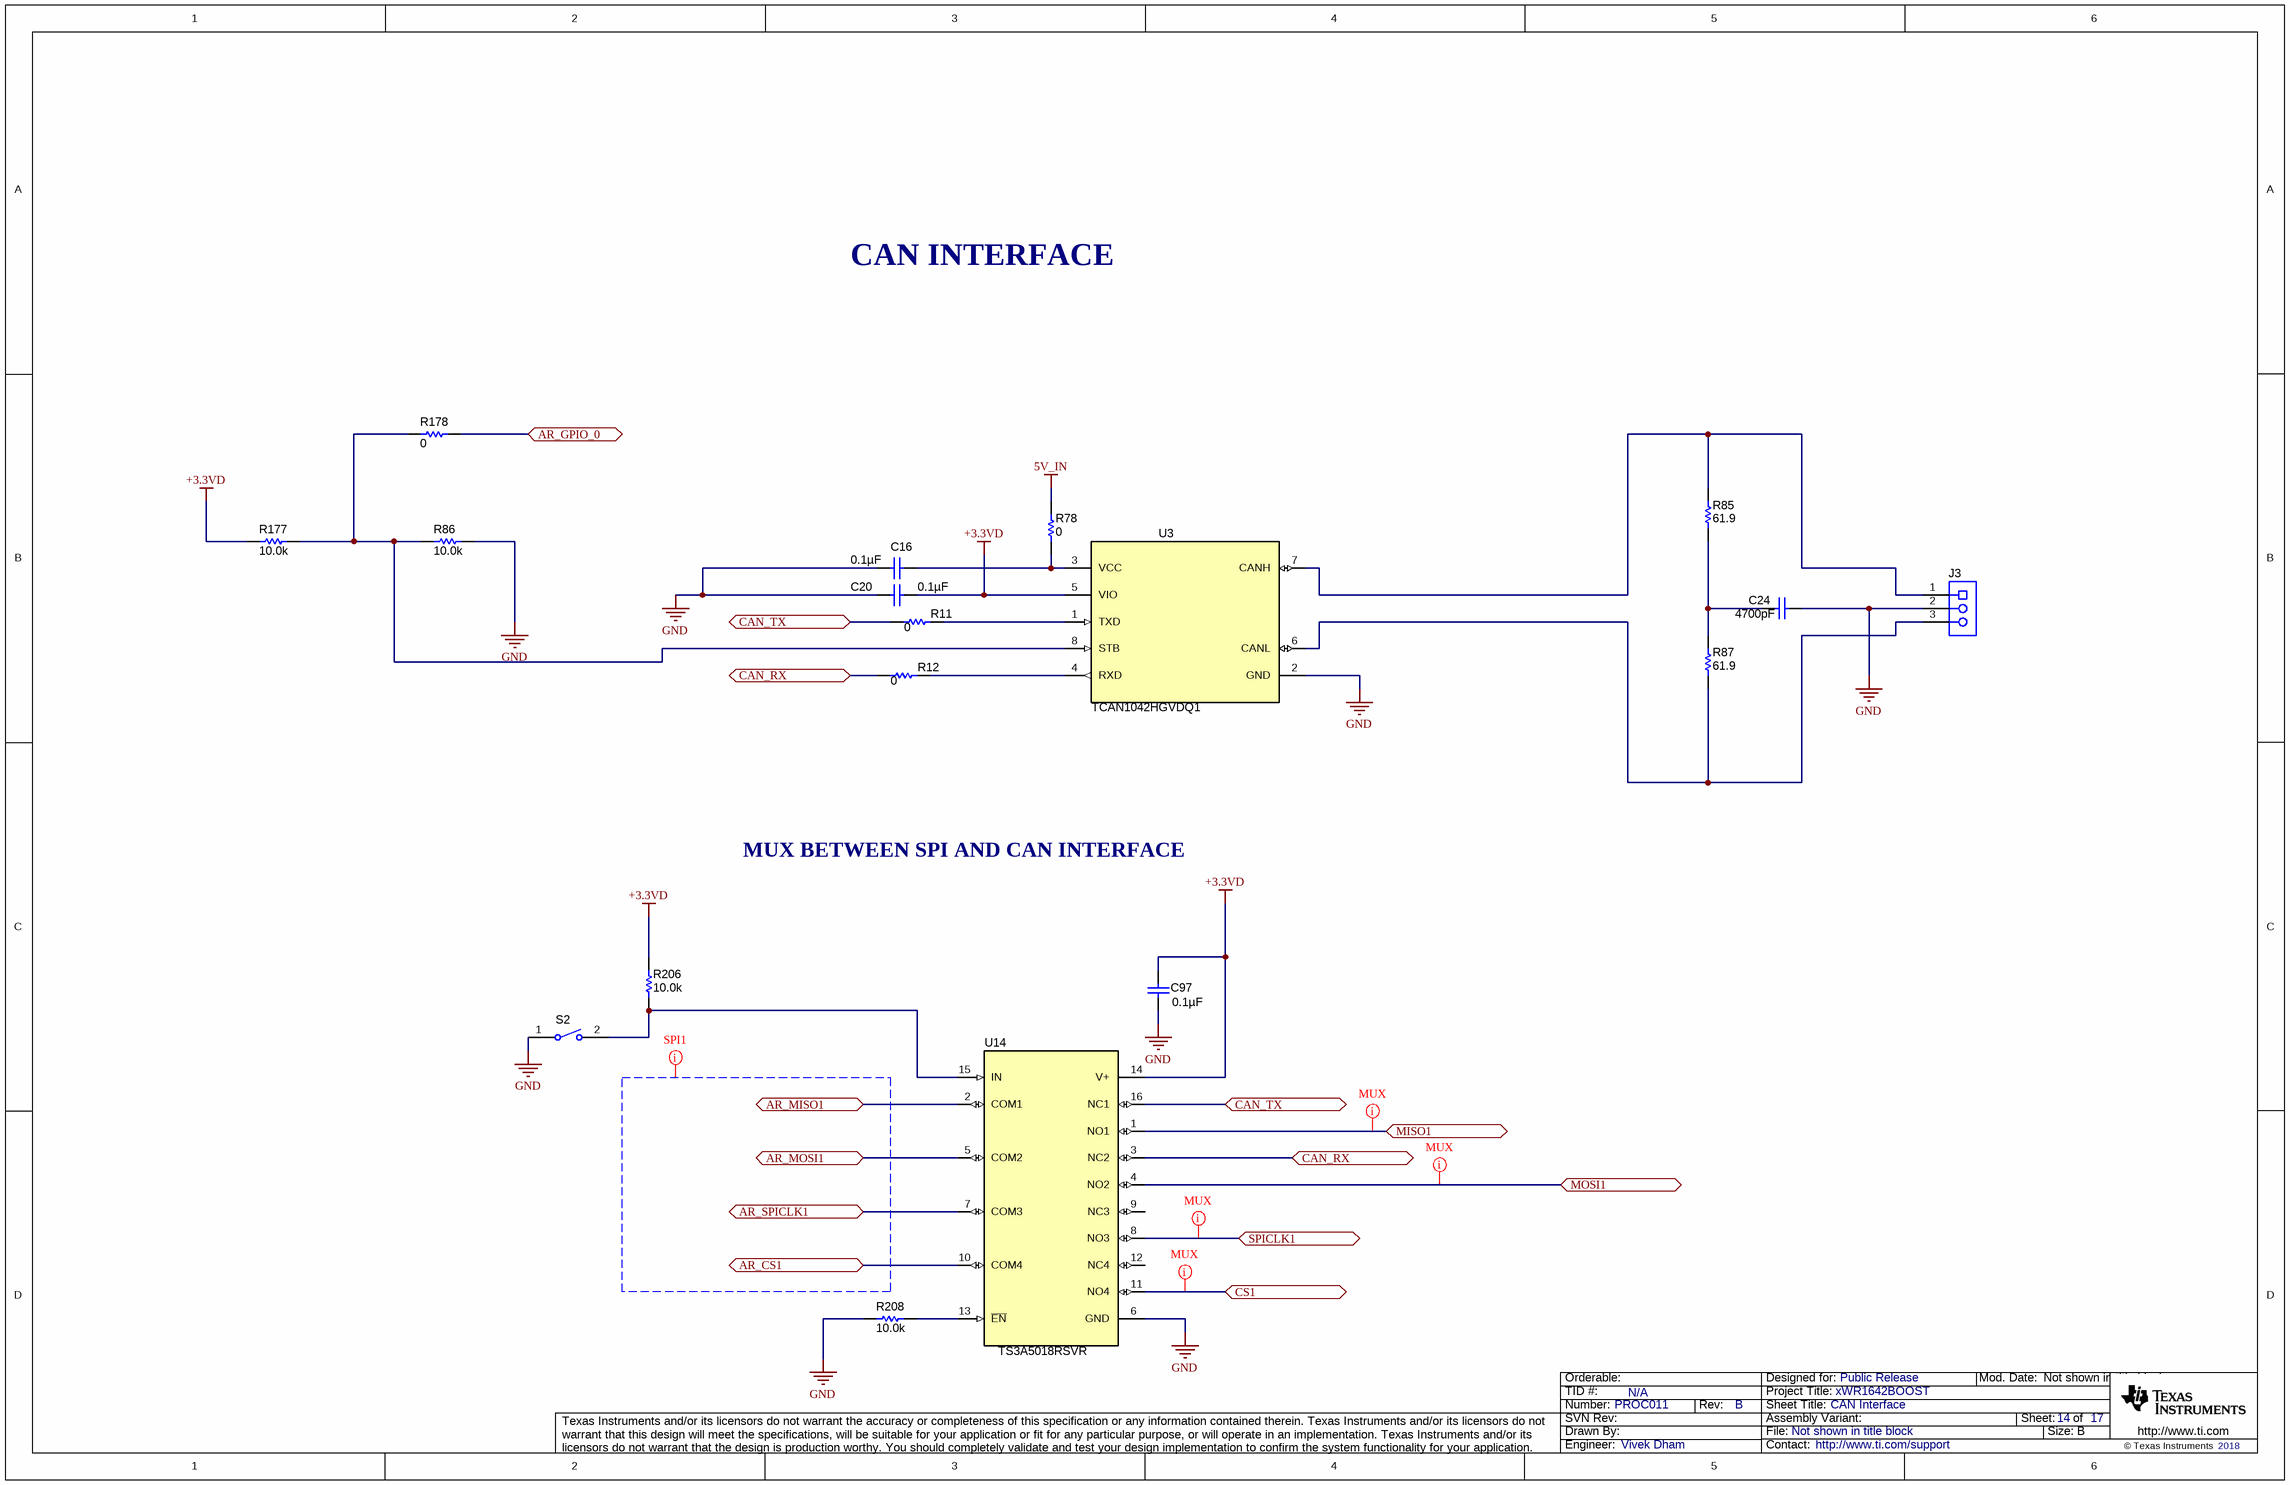
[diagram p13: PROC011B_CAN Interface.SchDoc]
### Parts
C16  ValueDisplayed: 0.1µF  [0402L]  (hidden comment: C0402C104K8RACTU)
C20  ValueDisplayed: 0.1µF  [0402L]  (hidden comment: C0402C104K8RACTU)
C24  ValueDisplayed: 4700pF  [0402L]  (hidden comment: C1005X7R1H472K050BA)
C97  ValueDisplayed: 0.1µF  [0402L]  (hidden comment: C0402C104K8RACTU)
J3  OSTTE030161  [On-Shore_OSTTE030161]  (value not drawn)
R11  ValueDisplayed: 0  [0402L]  (hidden comment: ERJ-2GE0R00X)
R12  ValueDisplayed: 0  [0402L]  (hidden comment: ERJ-2GE0R00X)
R78  ValueDisplayed: 0  [0402L]  (hidden comment: ERJ-2GE0R00X)
R85  ValueDisplayed: 61.9  [0402L]  (hidden comment: CRCW040261R9FKED)
R86  ValueDisplayed: 10.0k  [0402L]  (hidden comment: CRCW040210K0FKED)
R87  ValueDisplayed: 61.9  [0402L]  (hidden comment: CRCW040261R9FKED)
R177  ValueDisplayed: 10.0k  [0402L]  (hidden comment: CRCW040210K0FKED)
R178  ValueDisplayed: 0  [0402L]  (hidden comment: ERJ-2GE0R00X)
R206  ValueDisplayed: 10.0k  [0402L]  (hidden comment: CRCW040210K0FKED)
R208  ValueDisplayed: 10.0k  [0402L]  (hidden comment: CRCW040210K0FKED)
S2  CHS-01TB  [SW_CHS-01TB]  (value not drawn)
U3  TCAN1042HGVDQ1  [D0008A_L]
U14  TS3A5018RSVR  [RSV0016A]

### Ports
AR_CS1, AR_GPIO_0, AR_MISO1, AR_MOSI1, AR_SPICLK1, CAN_RX, CAN_TX, CS1, MISO1, MOSI1, SPICLK1

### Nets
5V_IN: R78.2
+3.3VD: C20.2 C97.2 R177.1 R206.2 U3.5(VIO) U14.14(V+)
GND: C16.1 C20.1 C24.1 C97.1 J3.2 R86.2 R208.2 S2.1 U3.2(GND) U14.6(GND)
AR_CS1: U14.10(COM4) ; port AR_CS1
AR_GPIO_0: R178.2 ; port AR_GPIO_0
AR_MISO1: U14.2(COM1) ; port AR_MISO1
AR_MOSI1: U14.5(COM2) ; port AR_MOSI1
AR_SPICLK1: U14.7(COM3) ; port AR_SPICLK1
CAN_RX: R12.1 U14.3(NC2) ; port CAN_RX
CAN_TX: R11.1 U14.16(NC1) ; port CAN_TX
CS1: U14.11(NO4) ; port CS1
MISO1: U14.1(NO1) ; port MISO1
MOSI1: U14.4(NO2) ; port MOSI1
SPICLK1: U14.8(NO3) ; port SPICLK1
NetC16_2: C16.2 R78.1 U3.3(VCC)
NetC24_2: C24.2 R85.1 R87.2
NetJ3_1: J3.1 R85.2 U3.7(CANH)
NetJ3_3: J3.3 R87.1 U3.6(CANL)
NetR11_2: R11.2 U3.1(TXD)
NetR12_2: R12.2 U3.4(RXD)
NetR86_1: R86.1 R177.2 R178.1 U3.8(STB)
NetR206_1: R206.1 S2.2 U14.15(IN)
NetR208_1: R208.1 U14.13(~{EN})

Not connected (* = marked no-connect by the designer): U14 9(NC3) 12(NC4)

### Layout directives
net class MUX_TO_J1: CS1, MISO1, MOSI1, SPICLK1
net class SPI1: (no net found under the mark)

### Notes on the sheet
- CAN INTERFACE
- MUX BETWEEN SPI AND CAN INTERFACE

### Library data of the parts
C16 C20 C97 = CMP-0078241-1: CAP, CERM, 0.1 µF, 10 V,+/- 10%, X7R, 0402; Manufacturer: Kemet; TaMin_C: -55°C; Polarized: N; SizeAreaWB_mm2: 3; U/M: EA; Value: 0.1uF; TaMax_C: 125°C; SizeZ_mm: 0.6; SizeX_mm: 1; SizeY_mm: 0.5; Cap_Case: 0402; Value2: 10V; Cap_F: 100nF; AEC Category: Q200
C24 = CMP-0078221-1: CAP, CERM, 4700 pF, 50 V,+/- 10%, X7R, 0402; Manufacturer: TDK; TaMin_C: -55°C; Polarized: N; SizeAreaWB_mm2: 3; U/M: EA; Value: 4700pF; TaMax_C: 125°C; SizeZ_mm: 0.6; SizeX_mm: 1; SizeY_mm: 0.5; Cap_Case: 0402; Value2: 50V; Cap_F: 4.7nF; AEC Category: Q200
J3 = CMP-0075352-1: Terminal Block, 3.5mm, 3x1, Tin, R/A, TH; Manufacturer: On-Shore Technology; CNHeader: False; Current_A: 10A; Green_Lifecycle: Not Set; Gender: Female; Cert_CSA: Y; Green_REACh: Incomplete; Voltage_V: 125V; Row_Count: 1; Pitch_mm: 3.5; CT: True
R11 R12 R178 = CMP-0026992-2: RES, 0, 5%, 0.063 W, 0402; Manufacturer: Panasonic; Power_W: 63mW; TempCo: 600 ppm/C; Value_Code: 0000; U/M: EA; Value: 0; EIA_Code: E24; SizeX_mm: 1; SizeY_mm: 0.5; SizeZ_mm: 0.6; Value2: 0.063W; CompType: Resistor; VDC_V: 50V; AEC Category: Q200; INSTALATION: DNP
R78 = CMP-0026992-2: RES, 0, 5%, 0.063 W, 0402; Manufacturer: Panasonic; Power_W: 63mW; TempCo: 600 ppm/C; Value_Code: 0000; U/M: EA; Value: 0; EIA_Code: E24; SizeX_mm: 1; SizeY_mm: 0.5; SizeZ_mm: 0.6; Value2: 0.063W; VDC_V: 50V; AEC Category: Q200
R85 R87 = CMP-0026491-1: RES, 61.9, 1%, 0.063 W, 0402; Manufacturer: Vishay-Dale; Power_W: 63mW; TempCo: 100 ppm/C; Value_Code: 61R9; U/M: EA; Value: 61.9; EIA_Code: E96; SizeX_mm: 1; SizeY_mm: 0.5; SizeZ_mm: 0.6; Value2: 0.063W; VDC_V: 50V; AEC Category: Q200
R86 = CMP-0025958-2: RES, 10.0 k, 1%, 0.063 W, 0402; Manufacturer: Vishay-Dale; Power_W: 63mW; TempCo: 100 ppm/C; Value_Code: 10k0; U/M: EA; Value: 10.0k; EIA_Code: E96; Res_ohm: 10k; SizeX_mm: 1; SizeY_mm: 0.5; SizeZ_mm: 0.6; Value2: 0.063W; VDC_V: 50V; AEC Category: Q200
R177 = CMP-0025958-2: RES, 10.0 k, 1%, 0.063 W, 0402; Manufacturer: Vishay-Dale; Power_W: 63mW; TempCo: 100 ppm/C; Value_Code: 10k0; U/M: EA; Value: 10.0k; EIA_Code: E96; Res_ohm: 10k; SizeX_mm: 1; SizeY_mm: 0.5; SizeZ_mm: 0.6; Value2: 0.063W; CompType: Resistor; VDC_V: 50V; AEC Category: Q200; INSTALATION: DNP
R206 R208 = CMP-0025958-2: RES, 10.0 k, 1%, 0.063 W, 0402; Manufacturer: Vishay-Dale; Power_W: 63mW; TempCo: 100 ppm/C; Value_Code: 10k0; U/M: EA; Value: 10.0k; EIA_Code: E96; Res_ohm: 10k; SizeX_mm: 1; SizeY_mm: 0.5; SizeZ_mm: 0.6; Value2: 0.063W; CompType: Resistor; VDC_V: 50V; AEC Category: Q200
S2 = CMP-0002163-2: Switch, Slide, SPST, Top Slide, SMT; Manufacturer: Copal Electronics; CurrentRating_mA: 100A; SwitchFunction: Off-On; VDC_V: 6V; PositionCount: 1
U3 = CMP-0075992-1: Automotive Fault Protected CAN Transceiver With Flexible Data-Rate, D0008A (SOIC-8); Manufacturer: Texas Instruments; Alternate PartNumber: TCAN1042HGVDRQ1; SizeAreaWB_mm2: 56.58; SizeArea_mm2: 30.38; SizeZ_mm: 1.75; SizeY_mm: 6.2; U/M: EA; CompType: IC; SizeX_mm: 4.9
U14 = CMP-0067415-1: 10-Ohm Quad SPDT Analog Switch, RSV0016A (UQFN-16); Alternate Manufacturer: Texas Instruments; SizeAreaWB_mm2: 10.08; U/M: EA; SizeZ_mm: 0.55; SizeX_mm: 1.8; SizeY_mm: 2.6; SizeArea_mm2: 4.68; CompType: IC

## Sheet PROC011B_SOP selection.SchDoc: SOP selection
size 431 x 279 mm; Date: Not shown in title block; ApprovedBy: Not shown in title block; CheckedBy: Not shown in title block; Author: Not shown in title block; CompanyName: Not shown in title block; Engineer: Not shown in title block; Organization: Not shown in title block; Address1: Not shown in title block; Address2: Not shown in title block; Address3: Not shown in title block; Address4: Not shown in title block; DocumentNumber: 1; Revision: Use project parameter SCH_Rev; SheetNumber: 15; SheetTotal: 17; PageSetup: Record=PageOptions¦CenterHorizontal=True¦CenterVertical=True¦PrintScale=1.00¦XCorrection=1.00¦YCorrection=1.00¦PrintKind=0¦BorderSize=5000000¦LeftOffset=0¦BottomOffset=0¦Orientation=2¦PaperLength=1000¦PaperWidth=1000¦Scale=100¦PaperSource=15¦PrintQuality=600¦MediaType=1¦DitherType=10¦PaperKind=Letter¦PrintScaleMode=1

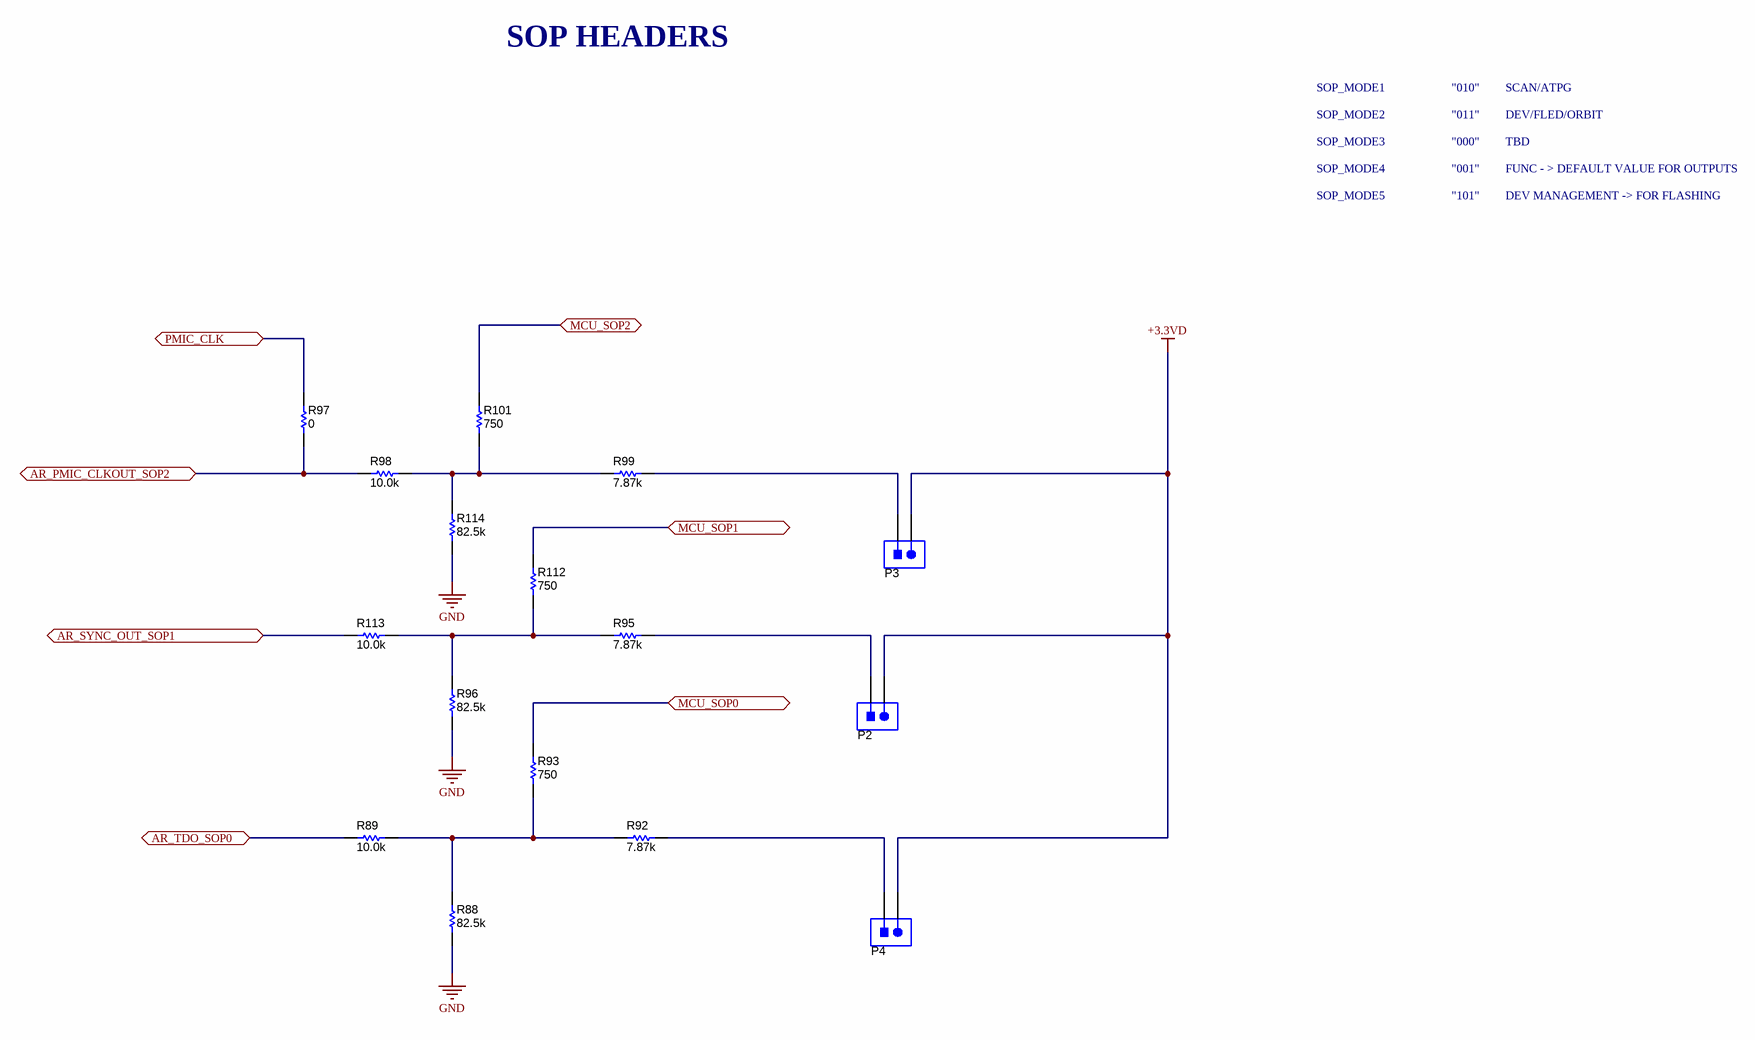
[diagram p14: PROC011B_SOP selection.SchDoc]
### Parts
P2  TSW-102-07-G-S  [TSW-102-07-X-S]  (value not drawn)
P3  TSW-102-07-G-S  [TSW-102-07-X-S]  (value not drawn)
P4  TSW-102-07-G-S  [TSW-102-07-X-S]  (value not drawn)
R88  ValueDisplayed: 82.5k  [0402L]  (hidden comment: CRCW040282K5FKED)
R89  ValueDisplayed: 10.0k  [0402L]  (hidden comment: CRCW040210K0FKED)
R92  ValueDisplayed: 7.87k  [0402L]  (hidden comment: CRCW04027K87FKED)
R93  ValueDisplayed: 750  [0402L]  (hidden comment: CRCW0402750RFKED)
R95  ValueDisplayed: 7.87k  [0402L]  (hidden comment: CRCW04027K87FKED)
R96  ValueDisplayed: 82.5k  [0402L]  (hidden comment: CRCW040282K5FKED)
R97  ValueDisplayed: 0  [0402L]  (hidden comment: ERJ-2GE0R00X)
R98  ValueDisplayed: 10.0k  [0402L]  (hidden comment: CRCW040210K0FKED)
R99  ValueDisplayed: 7.87k  [0402L]  (hidden comment: CRCW04027K87FKED)
R101  ValueDisplayed: 750  [0402L]  (hidden comment: CRCW0402750RFKED)
R112  ValueDisplayed: 750  [0402L]  (hidden comment: CRCW0402750RFKED)
R113  ValueDisplayed: 10.0k  [0402L]  (hidden comment: CRCW040210K0FKED)
R114  ValueDisplayed: 82.5k  [0402L]  (hidden comment: CRCW040282K5FKED)

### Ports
AR_PMIC_CLKOUT_SOP2, AR_SYNC_OUT_SOP1, AR_TDO_SOP0, MCU_SOP0, MCU_SOP1, MCU_SOP2, PMIC_CLK

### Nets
+3.3VD: P2.2 P3.2 P4.2
GND: R88.1 R96.1 R114.1
AR_PMIC_CLKOUT_SOP2: R97.1 R98.1 ; port AR_PMIC_CLKOUT_SOP2
AR_SYNC_OUT_SOP1: R113.1 ; port AR_SYNC_OUT_SOP1
AR_TDO_SOP0: R89.1 ; port AR_TDO_SOP0
MCU_SOP0: R93.2 ; port MCU_SOP0
MCU_SOP1: R112.2 ; port MCU_SOP1
MCU_SOP2: R101.2 ; port MCU_SOP2
PMIC_CLK: R97.2 ; port PMIC_CLK
NetP2_1: P2.1 R95.2
NetP3_1: P3.1 R99.2
NetP4_1: P4.1 R92.2
NetR88_2: R88.2 R89.2 R92.1 R93.1
NetR95_1: R95.1 R96.2 R112.1 R113.2
NetR98_2: R98.2 R99.1 R101.1 R114.2

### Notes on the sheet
- SOP HEADERS
- SOP_MODE1
- SOP_MODE2
- "010"
- "011"
- SCAN/ATPG
- DEV/FLED/ORBIT
- SOP_MODE3
- SOP_MODE4
- "000"
- "001"
- TBD
- FUNC - > DEFAULT VALUE FOR OUTPUTS
- SOP_MODE5
- "101"
- DEV MANAGEMENT -> FOR FLASHING

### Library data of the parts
P2-P4 = CMP-0075405-1: Header, 100mil, 2x1, Gold, TH; Manufacturer: Samtec; Pitch_mm: 2.54; Cert_VDE: N; Gender: Male; Cert_CSA: Y; Voltage_V: 550V; Green_REACh: Passed; Current_A: 6.3A; CT: False; Green_Lifecycle: Active; Row_Count: 1; CNHeader: True
R88 R96 R114 = CMP-0026574-1: RES, 82.5 k, 1%, 0.063 W, AEC-Q200 Grade 0, 0402; Manufacturer: Vishay-Dale; Power_W: 63mW; TempCo: 100 ppm/C; Value_Code: 82k5; U/M: EA; Value: 82.5k; EIA_Code: E96; SizeX_mm: 1; SizeY_mm: 0.5; SizeZ_mm: 0.6; Value2: 0.063W; CompType: Resistor; AEC Qualified: Y; VDC_V: 50V; AEC Grade: 0; AEC Category: Q200
R89 R98 R113 = CMP-0025958-2: as R86 on sheet PROC011B_CAN Interface
R92 = CMP-0026557-1: RES, 7.87 k, 1%, 0.063 W, AEC-Q200 Grade 0, 0402; Manufacturer: Vishay-Dale; Power_W: 63mW; TempCo: 100 ppm/C; Value_Code: 7k87; U/M: EA; Value: 7.87k; EIA_Code: E96; SizeX_mm: 1; SizeY_mm: 0.5; SizeZ_mm: 0.6; Value2: 0.063W; CompType: Resistor; AEC Qualified: Y; VDC_V: 50V; AEC Grade: 0; AEC Category: Q200
R93 R101 R112 = CMP-0026542-1: RES, 750, 1%, 0.063 W, AEC-Q200 Grade 0, 0402; Manufacturer: Vishay-Dale; Power_W: 63mW; TempCo: 100 ppm/C; Value_Code: 750R; U/M: EA; Value: 750; EIA_Code: E96; SizeX_mm: 1; SizeY_mm: 0.5; SizeZ_mm: 0.6; Value2: 0.063W; AEC Qualified: Y; VDC_V: 50V; AEC Grade: 0; AEC Category: Q200
R95 R99 = CMP-0026557-1: RES, 7.87 k, 1%, 0.063 W, AEC-Q200 Grade 0, 0402; Manufacturer: Vishay-Dale; Power_W: 63mW; TempCo: 100 ppm/C; Value_Code: 7k87; U/M: EA; Value: 7.87k; EIA_Code: E96; SizeX_mm: 1; SizeY_mm: 0.5; SizeZ_mm: 0.6; Value2: 0.063W; AEC Qualified: Y; VDC_V: 50V; AEC Grade: 0; AEC Category: Q200
R97 = CMP-0026992-2: as R11 on sheet PROC011B_CAN Interface

## Sheet PROC011B_Tempsensor.SchDoc: Tempsensor
size 431 x 279 mm; Date: Not shown in title block; ApprovedBy: Not shown in title block; CheckedBy: Not shown in title block; Author: Not shown in title block; CompanyName: Not shown in title block; Engineer: Not shown in title block; Organization: Not shown in title block; Address1: Not shown in title block; Address2: Not shown in title block; Address3: Not shown in title block; Address4: Not shown in title block; DocumentNumber: 1; Revision: Use project parameter SCH_Rev; SheetNumber: 16; SheetTotal: 17; PageSetup: Record=PageOptions¦CenterHorizontal=True¦CenterVertical=True¦PrintScale=1.00¦XCorrection=1.00¦YCorrection=1.00¦PrintKind=0¦BorderSize=5000000¦LeftOffset=0¦BottomOffset=0¦Orientation=2¦PaperLength=1000¦PaperWidth=1000¦Scale=100¦PaperSource=15¦PrintQuality=600¦MediaType=1¦DitherType=10¦PaperKind=Letter¦PrintScaleMode=1

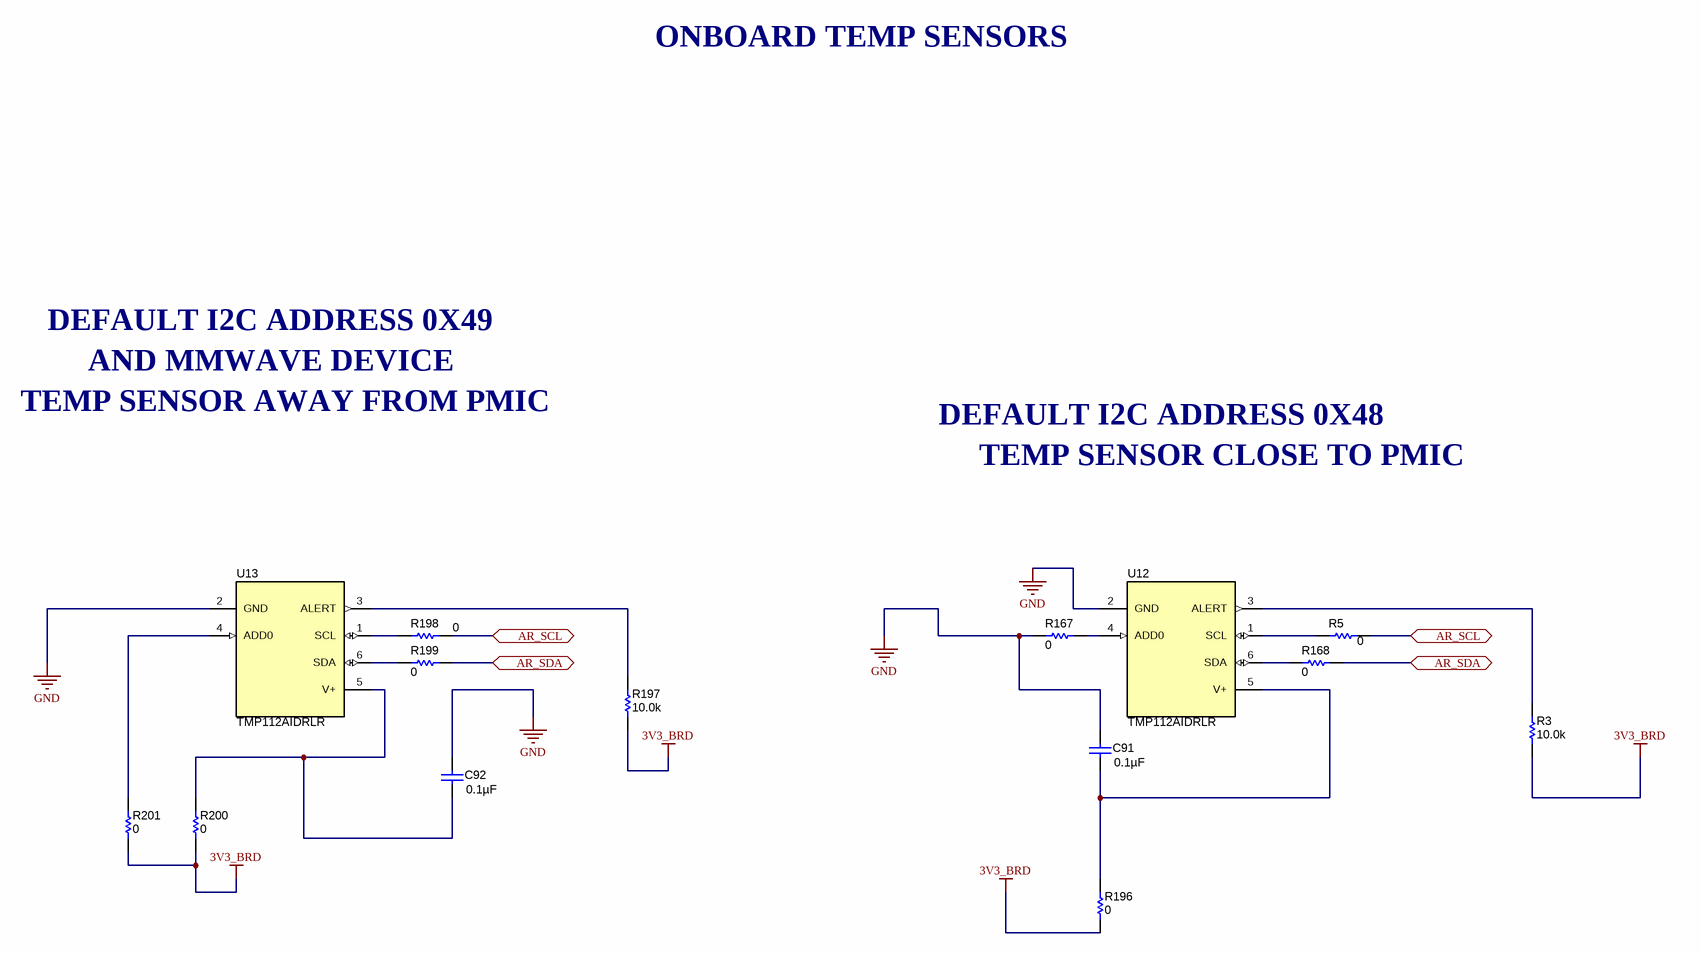
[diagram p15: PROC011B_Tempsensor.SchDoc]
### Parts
C91  ValueDisplayed: 0.1µF  [0402L]  (hidden comment: C0402C104K8RACTU)
C92  ValueDisplayed: 0.1µF  [0402L]  (hidden comment: C0402C104K8RACTU)
R3  ValueDisplayed: 10.0k  [0402L]  (hidden comment: CRCW040210K0FKED)
R5  ValueDisplayed: 0  [0201_Silk]  (hidden comment: CRCW02010000Z0ED)
R167  ValueDisplayed: 0  [0201_Silk]  (hidden comment: CRCW02010000Z0ED)
R168  ValueDisplayed: 0  [0201_Silk]  (hidden comment: CRCW02010000Z0ED)
R196  ValueDisplayed: 0  [0402L]  (hidden comment: ERJ-2GE0R00X)
R197  ValueDisplayed: 10.0k  [0402L]  (hidden comment: CRCW040210K0FKED)
R198  ValueDisplayed: 0  [0201_Silk]  (hidden comment: CRCW02010000Z0ED)
R199  ValueDisplayed: 0  [0201_Silk]  (hidden comment: CRCW02010000Z0ED)
R200  ValueDisplayed: 0  [0402L]  (hidden comment: ERJ-2GE0R00X)
R201  ValueDisplayed: 0  [0201_Silk]  (hidden comment: CRCW02010000Z0ED)
U12  TMP112AIDRLR  [DRL0006A]
U13  TMP112AIDRLR  [DRL0006A]

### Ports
AR_SCL, AR_SDA

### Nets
3V3_BRD: R3.2 R196.2 R197.2 R200.2 R201.2
GND: C91.1 C92.1 R167.1 U12.2(GND) U13.2(GND)
AR_SCL: R5.1 R198.1 ; port AR_SCL
AR_SDA: R168.2 R199.2 ; port AR_SDA
NetC91_2: C91.2 R196.1 U12.5(V+)
NetC92_2: C92.2 R200.1 U13.5(V+)
NetR3_1: R3.1 U12.3(ALERT)
NetR5_2: R5.2 U12.1(SCL)
NetR167_2: R167.2 U12.4(ADD0)
NetR168_1: R168.1 U12.6(SDA)
NetR197_1: R197.1 U13.3(ALERT)
NetR198_2: R198.2 U13.1(SCL)
NetR199_1: R199.1 U13.6(SDA)
NetR201_1: R201.1 U13.4(ADD0)

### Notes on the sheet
- ONBOARD TEMP SENSORS
- DEFAULT I2C ADDRESS 0X49
- AND MMWAVE DEVICE
- TEMP SENSOR AWAY FROM PMIC
- DEFAULT I2C ADDRESS 0X48
- TEMP SENSOR CLOSE TO PMIC

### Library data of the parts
C91 C92 = CMP-0078241-1: as C16 on sheet PROC011B_CAN Interface
R3 R197 = CMP-0025958-2: as R86 on sheet PROC011B_CAN Interface
R5 R167 R168 R198 R199 R201 = CMP-0027008-3: RES, 0, 5%, 0.05 W, 0201; Manufacturer: Vishay-Dale; Power_W: 50mW; TempCo: ppm/C; Value_Code: 0000; U/M: EA; Value: 0; EIA_Code: E24; SizeX_mm: 0.6; SizeY_mm: 0.3; SizeZ_mm: 0.26; Value2: 0.05W; SizeArea_mm2: 0.18; AEC Qualified: N; AEC Category: Q200
R196 R200 = CMP-0026992-2: as R78 on sheet PROC011B_CAN Interface
U12 U13 = CMP-0067397-2: 1.4V-Capable +/-0.5degC Temperature Sensor with Alert Function and I2C/SMBus interface in SOT-563, DRL0006A (SOT-OTHER-6); Alternate PartNumber: TMP112AIDRLT; Alternate Manufacturer: Texas Instruments; Green_Lifecycle: Active; SizeAreaWB_mm2: 6.76; Green_REACh: Passed; U/M: EA; SizeZ_mm: 0.6; SizeX_mm: 1.6; SizeArea_mm2: 2.56; CompType: IC

## Sheet PROC011B_Hardware.SchDoc: Hardware
size 431 x 279 mm; Date: Not shown in title block; ApprovedBy: Not shown in title block; CheckedBy: Not shown in title block; Author: Not shown in title block; CompanyName: Not shown in title block; Engineer: Not shown in title block; Organization: Not shown in title block; Address1: Not shown in title block; Address2: Not shown in title block; Address3: Not shown in title block; Address4: Not shown in title block; DocumentNumber: 1; Revision: Use project parameter SCH_Rev; SheetNumber: 17; SheetTotal: 17; PageSetup: Record=PageOptions¦CenterHorizontal=True¦CenterVertical=True¦PrintScale=1.00¦XCorrection=1.00¦YCorrection=1.00¦PrintKind=0¦BorderSize=5000000¦LeftOffset=0¦BottomOffset=0¦Orientation=2¦PaperLength=1000¦PaperWidth=1000¦Scale=100¦PaperSource=15¦PrintQuality=600¦MediaType=1¦DitherType=10¦PaperKind=Letter¦PrintScaleMode=1

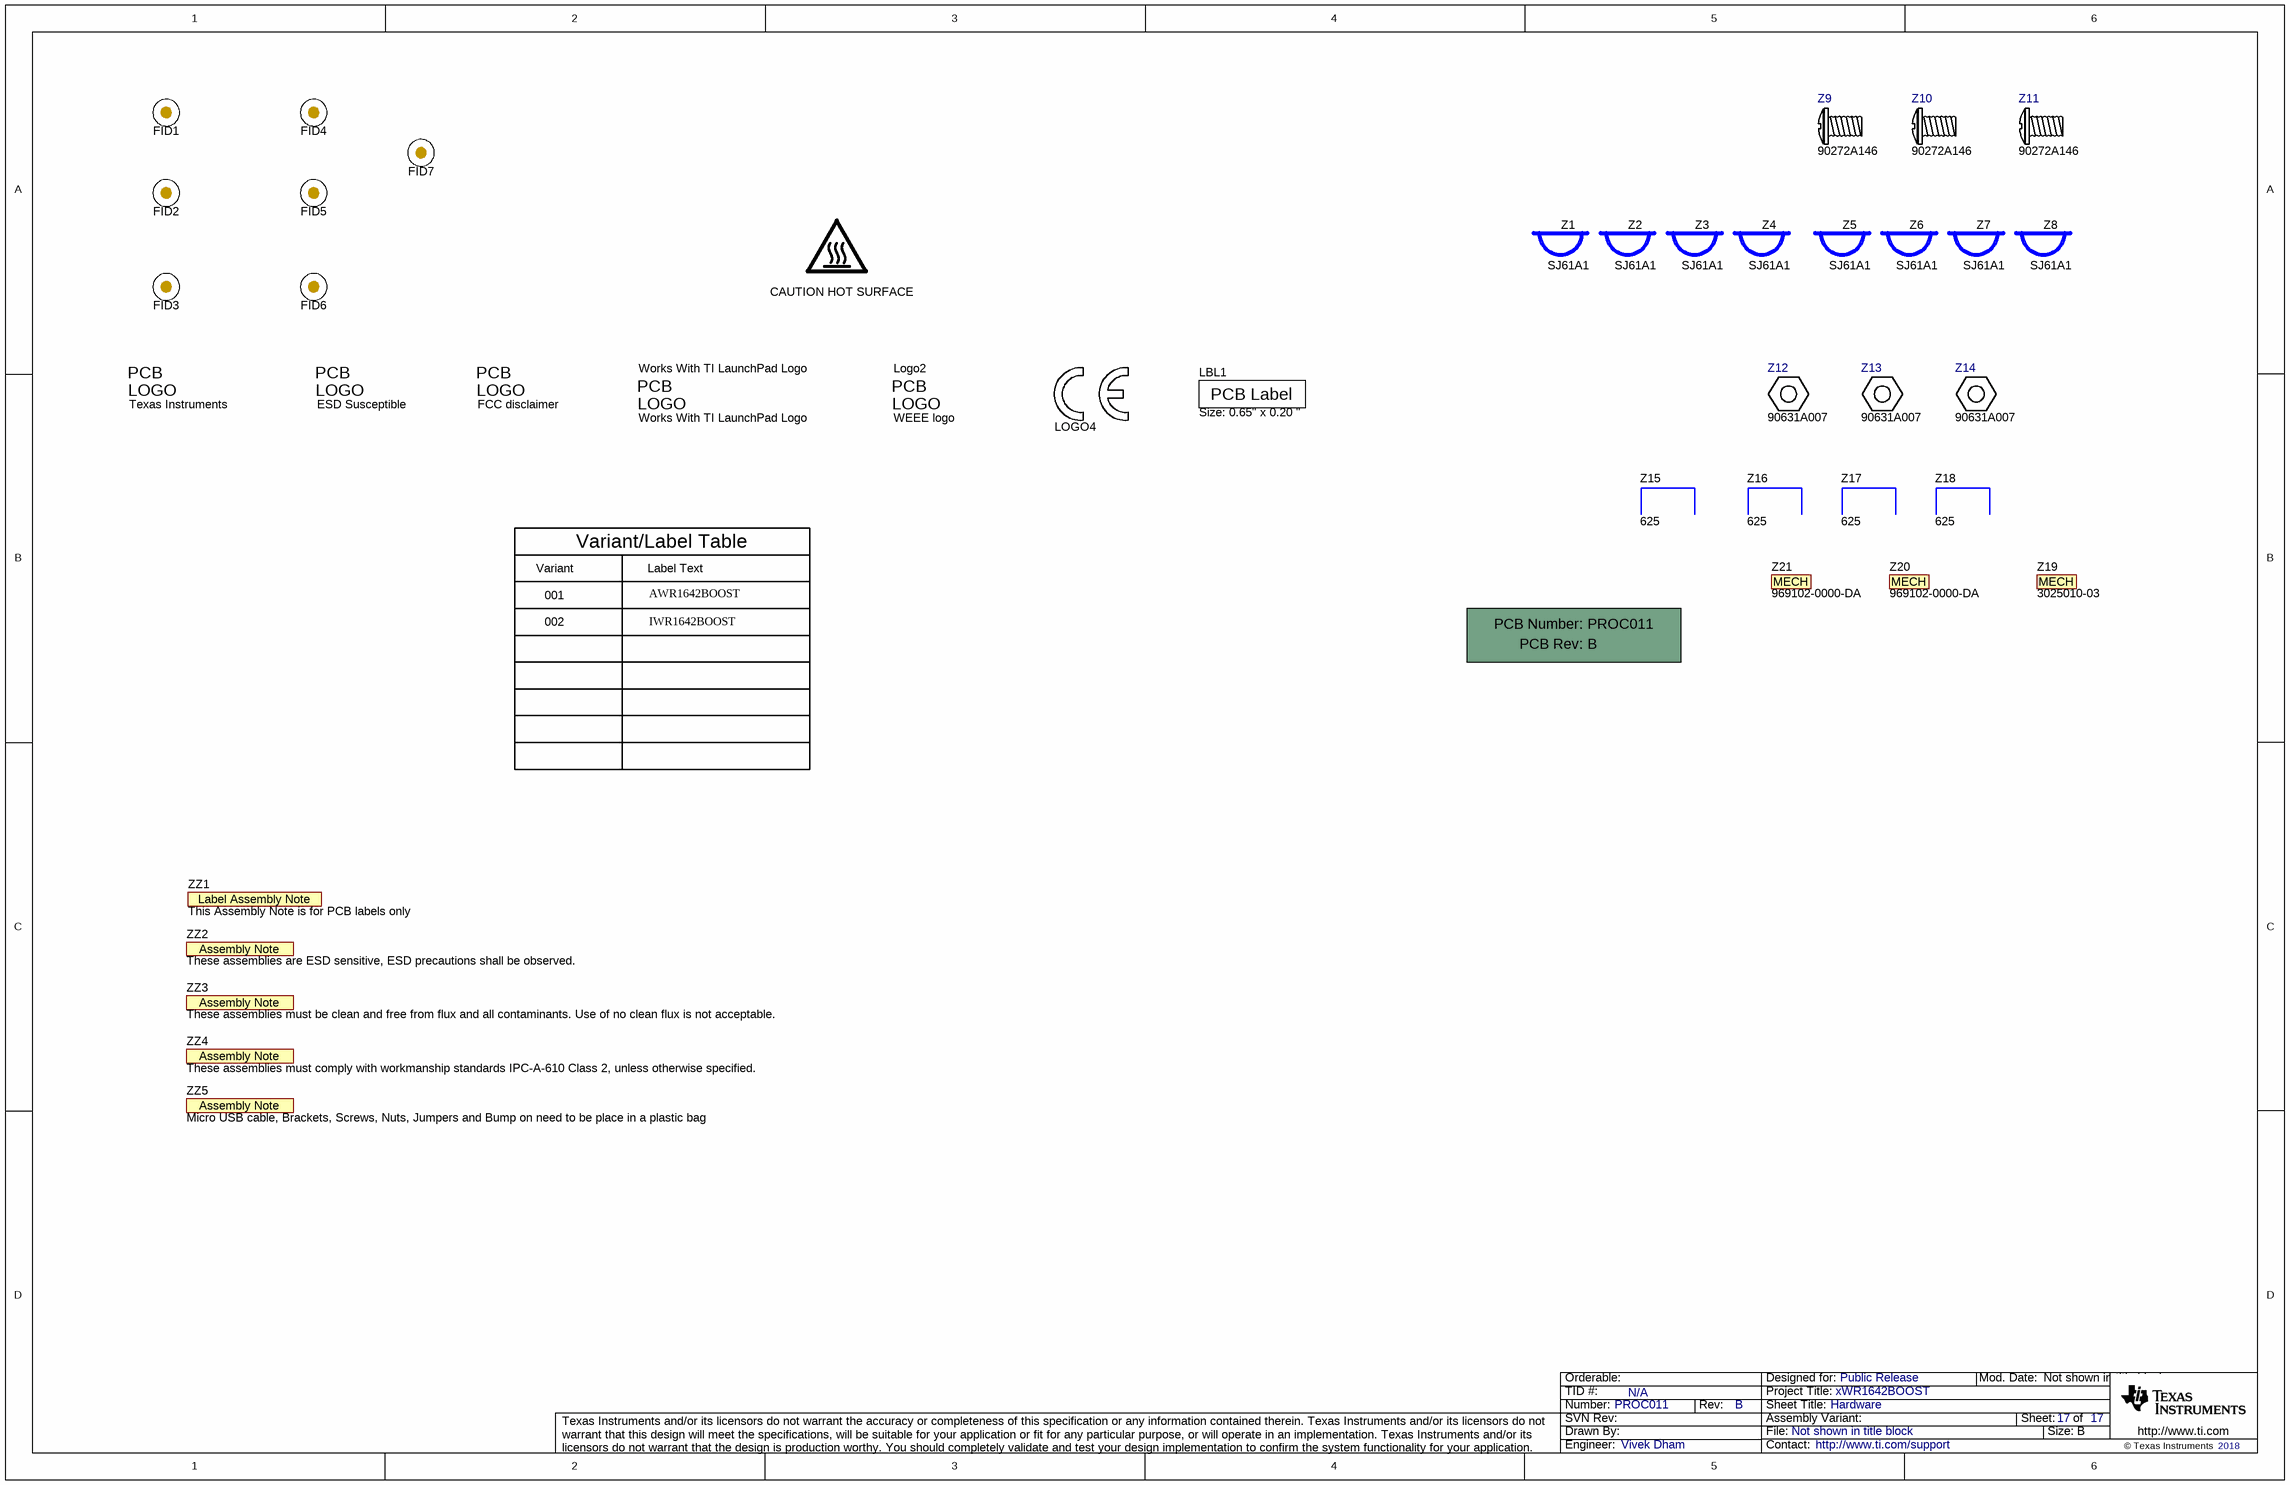
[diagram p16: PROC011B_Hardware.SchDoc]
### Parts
!PCB  PROC011  (value not drawn)  (mechanical)
CAUTION_HOT_SURFACE  CAUTION HOT SURFACE  [IEC_HotSurface_Small]  (no BOM)
ESD_Susceptible  ESD Susceptible  [ESD_Overlay_Small]  (no BOM)
FID1  Fiducial  [Fiducial10-20]  (value not drawn)
FID2  Fiducial  [Fiducial10-20]  (value not drawn)
FID3  Fiducial  [Fiducial10-20]  (value not drawn)
FID4  Fiducial  [Fiducial10-20]  (value not drawn)
FID5  Fiducial  [Fiducial10-20]  (value not drawn)
FID6  Fiducial  [Fiducial10-20]  (value not drawn)
FID7  Fiducial  [Fiducial10-20]  (value not drawn)
LBL1  Size: 0.65" x 0.20 "  [Label_650x200]
Logo1  Texas Instruments  [TI_Stacked_Overlay_Small]  (no BOM)
Logo2  WEEE logo  [WEEE_Minimum]  (no BOM)
Logo3  FCC disclaimer  [FCC_disclaimer]  (no BOM)
LOGO4  CE Mark  [CE_Mark_5mm]  (value not drawn)  (no BOM)
Works_With_TI_LaunchPad_Logo  Works With TI LaunchPad Logo  [WorksWithTILaunchPad]  (mechanical)
Z1  SJ61A1  (mechanical)
Z2  SJ61A1  (mechanical)
Z3  SJ61A1  (mechanical)
Z4  SJ61A1  (mechanical)
Z5  SJ61A1  (mechanical)
Z6  SJ61A1  (mechanical)
Z7  SJ61A1  (mechanical)
Z8  SJ61A1  (mechanical)
Z9  90272A146  (mechanical)
Z10  90272A146  (mechanical)
Z11  90272A146  (mechanical)
Z12  90631A007  (mechanical)
Z13  90631A007  (mechanical)
Z14  90631A007  (mechanical)
Z15  625  (mechanical)
Z16  625  (mechanical)
Z17  625  (mechanical)
Z18  625  (mechanical)
Z19  3025010-03  (mechanical)
Z20  969102-0000-DA  (mechanical)
Z21  969102-0000-DA  (mechanical)
ZZ1  This Assembly Note is for PCB labels only  [AssemblyNoteLabel]  (no BOM)
ZZ2  These assemblies are ESD sensitive, ESD precautions shall be observed.  [AssemblyNote]  (no BOM)
ZZ3  These assemblies must be clean and free from flux and all contaminants. Use of no clean flux is not acceptable.  [AssemblyNote]  (no BOM)
ZZ4  These assemblies must comply with workmanship standards IPC-A-610 Class 2, unless otherwise specified.  [AssemblyNote]  (no BOM)
ZZ5  Micro USB cable, Brackets, Screws, Nuts, Jumpers and Bump on need to be place in a plastic bag  [AssemblyNote]  (no BOM)

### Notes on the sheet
- Variant
- Variant/Label Table
- Label Text
- 001
- 002
- AWR1642BOOST
- IWR1642BOOST

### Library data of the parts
!PCB = CMP-0003618-2: Printed Circuit Board; Manufacturer: Any; CompType: PCB
CAUTION_HOT_SURFACE = CMP-0074837-1: IEC 61010-1 Hot Surface Warning; Library Reference: IEC_HotSurface; SymbolCreator: a0412235
ESD_Susceptible = CMP-0074840-1: ESD Susceptible Symbol; Library Reference: Logo; SymbolCreator: a0412235; Lib Reference: ESD_Susceptible
FID1-FID7 = CMP-0077181-1: Fiducial mark.  There is nothing to buy or mount.
LBL1 = THT-14-423-10: Thermal Transfer Printable Labels, 0.650" W x 0.200" H - 10,000 per roll; Manufacturer: Brady; SymbolCreator: a0412235; CompType: Label
Logo1 = CMP-0074838-1: Texas Instrument Corporate Signature; SymbolCreator: a0412235; Lib Reference: TI_Logo; Library Reference: Logo
Logo2 = CMP-0074769-1
Logo3 = CMP-0074847-1: FCC_disclaimer; Library Reference: Logo
LOGO4 = CE Mark: SymbolCreator: a0412235
Works_With_TI_LaunchPad_Logo = CMP-0077108-1
Z1-Z8 = SJ61A1: Bumpon, Cylindrical, 0.312 X 0.200, Black; Manufacturer: 3M; SymbolCreator: a0412235; Green_Lifecycle: Not Set; Green_REACh: Incomplete
Z9-Z11 = NY PMS 256 0050 PH: Screw, Pan Philips, Nylon, 2-56; Manufacturer: B&F Fastener Supply; SymbolCreator: a0412235
Z12-Z14 = HNSS 832: Nut, Hex, 11/32" Stainless Steel, 8-32; Manufacturer: mcmaster
Z15-Z18 = PCC-SMP-CLIP: BRACKET MOUNTIG ALUM; Manufacturer: Keystone Electronics; CompType: Hardware
Z19 = AK672M/2-1-R: CABLE MINI USB 5PIN 1M 2.0 VERS; CompType: CABLE USB
Z20 Z21 = 0050579402: 2 (1 x 2) Position Shunt Connector Black Open Top 0.100" (2.54mm) Gold
ZZ1 = AssemblyNoteLabel: SymbolCreator: a0412235
ZZ2-ZZ5 = AssemblyNote: SymbolCreator: codlsc

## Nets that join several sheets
3V3_BRD: PROC011B_XDS110 Interface_1A (11 pins), PROC011B_XDS110 Interface_1B (20 pins), PROC011B_Tempsensor (5 pins)
5V_IN: PROC011B_VPP_Supply (C86.2 R194.1 U11.1 U11.2), PROC011B_Pwr_RST_LEDs (7 pins), PROC011B_PMIC (R149.2), PROC011B_LP Connector (R115.2), PROC011B_HD Connector (R34.2), PROC011B_XDS110 Interface_1A (R176.2), PROC011B_CAN Interface (R78.2)
5V_UNREG: PROC011B_Pwr_RST_LEDs (P5.2 R118.2), PROC011B_PMIC (10 pins)
+3.3VD: PROC011B_DUT (U2.F15 U2.R10), PROC011B_Decoupling caps (C5.2 C84.2 C87.2), PROC011B_Pwr_RST_LEDs (6 pins), PROC011B_QSPI flash section (R37.1 R38.2 R41.2 R43.2), PROC011B_LP Connector (7 pins), PROC011B_CAN Interface (6 pins), PROC011B_SOP selection (P2.2 P3.2 P4.2)
AR_1P3_RF1: PROC011B_DUT (U2.G5 U2.H5 U2.J5), PROC011B_Decoupling caps (C45.2 C47.2 R195.2), PROC011B_LDO_02 (1.3V Output) (7 pins)
AR_1P3_RF2: PROC011B_DUT (U2.C2 U2.D2), PROC011B_Decoupling caps (5 pins), PROC011B_LDO_02 (1.3V Output) (7 pins)
AR_1V4_APLL: PROC011B_DUT (U2.A10), PROC011B_Decoupling caps (C13.2)
AR_1V4_SYNTH: PROC011B_DUT (U2.A13), PROC011B_Decoupling caps (C14.2)
AR_1V8: PROC011B_DUT (6 pins), PROC011B_Decoupling caps (9 pins), PROC011B_LDO_01 (1.8V Output) (5 pins)
AR_VBGAP: PROC011B_DUT (U2.B10), PROC011B_Decoupling caps (C56.2)
AR_VOUT_PA: PROC011B_DUT (U2.A2 U2.B2), PROC011B_Decoupling caps (C10.2 C65.2 C83.2 R137.2)
GND: PROC011B_DUT (68 pins), PROC011B_Decoupling caps (26 pins), PROC011B_LDO_01 (1.8V Output) (9 pins), PROC011B_LDO_02 (1.3V Output) (19 pins), PROC011B_VPP_Supply (5 pins), PROC011B_Pwr_RST_LEDs (14 pins), PROC011B_PMIC (20 pins), PROC011B_QSPI flash section (C1.1 C2.1 U1.4 U1.9), PROC011B_LP Connector (8 pins), PROC011B_HD Connector (14 pins), PROC011B_XDS110 Interface_1A (22 pins), PROC011B_XDS110 Interface_1B (21 pins), PROC011B_CAN Interface (10 pins), PROC011B_SOP selection (R88.1 R96.1 R114.1), PROC011B_Tempsensor (5 pins)
MCU_3V3: PROC011B_Pwr_RST_LEDs (R130.1), PROC011B_LP Connector (J4.3 J6.1)
PMIC_1V2: PROC011B_DUT (6 pins), PROC011B_Decoupling caps (5 pins), PROC011B_PMIC (C54.2 L1.2 U8.14)
PMIC_1V8: PROC011B_Decoupling caps (L6.1), PROC011B_LDO_02 (1.3V Output) (10 pins), PROC011B_PMIC (C81.2 L4.2 U8.1)
PMIC_2V3: PROC011B_Decoupling caps (L5.1), PROC011B_LDO_01 (1.8V Output) (6 pins), PROC011B_PMIC (C82.2 L3.2 U8.21)
PMICOUT_3V3: PROC011B_Pwr_RST_LEDs (R133.1), PROC011B_PMIC (C55.2 L2.2 R141.1 U8.8)
VDDC_1: PROC011B_XDS110 Interface_1A (C62.2 C64.2 C74.2 C75.2), PROC011B_XDS110 Interface_1B (U6.87 U6.115)
VPP_1P7: PROC011B_DUT (C8.2 U2.L13), PROC011B_VPP_Supply (P7.1)
XDSET_1_VBUS: PROC011B_XDS110 Interface_1A (R151.2 R161.2 U10.6), PROC011B_XDS110 Interface_1B (R154.2)
AR_ANAMUX: PROC011B_DUT (U2.B13), PROC011B_LP Connector (P1.3)
AR_ANATEST1: PROC011B_DUT (U2.P1), PROC011B_LP Connector (R104.2)
AR_ANATEST2: PROC011B_DUT (U2.P2), PROC011B_LP Connector (R94.2)
AR_ANATEST3: PROC011B_DUT (U2.P3), PROC011B_LP Connector (R105.2)
AR_ANATEST4: PROC011B_DUT (U2.R2), PROC011B_LP Connector (R106.2)
AR_BSS_LOGGER: PROC011B_DUT (U2.H14), PROC011B_LP Connector (R31.1), PROC011B_XDS110 Interface_1B (R135.1)
AR_CS1: PROC011B_DUT (U2.C13), PROC011B_CAN Interface (U14.10)
AR_DMM_CLK: PROC011B_DUT (U2.N15), PROC011B_HD Connector (R54.1)
AR_DMM_SYNC: PROC011B_DUT (U2.N14), PROC011B_HD Connector (R55.1)
AR_DP0: PROC011B_DUT (U2.R4), PROC011B_HD Connector (R56.1)
AR_DP1: PROC011B_DUT (U2.P5), PROC011B_HD Connector (R57.1)
AR_DP2: PROC011B_DUT (U2.R5), PROC011B_HD Connector (R179.1)
AR_DP3: PROC011B_DUT (U2.P6), PROC011B_HD Connector (R180.1)
AR_DP4: PROC011B_DUT (U2.R7), PROC011B_HD Connector (R181.1)
AR_DP5: PROC011B_DUT (U2.P7), PROC011B_HD Connector (R182.1)
AR_DP6: PROC011B_DUT (U2.R8), PROC011B_HD Connector (R183.1)
AR_DP7: PROC011B_DUT (U2.P8), PROC011B_LP Connector (R60.2), PROC011B_HD Connector (R184.1)
AR_DP8: PROC011B_DUT (U2.D14), PROC011B_HD Connector (R185.1)
AR_DP9: PROC011B_DUT (U2.B14), PROC011B_HD Connector (R186.1)
AR_DP10: PROC011B_DUT (U2.B15), PROC011B_HD Connector (R187.1)
AR_DP11: PROC011B_DUT (U2.C9), PROC011B_HD Connector (R188.1)
AR_DP12: PROC011B_DUT (U2.C8), PROC011B_HD Connector (R189.1)
AR_DP13: PROC011B_DUT (U2.B9), PROC011B_HD Connector (R190.1)
AR_DP14: PROC011B_DUT (U2.B8), PROC011B_HD Connector (R191.1)
AR_DP15: PROC011B_DUT (U2.A9), PROC011B_HD Connector (R192.1)
AR_GPIO_0: PROC011B_DUT (U2.H13), PROC011B_LP Connector (R164.1), PROC011B_CAN Interface (R178.2)
AR_GPIO_1: PROC011B_DUT (U2.J13), PROC011B_Pwr_RST_LEDs (R72.2), PROC011B_LP Connector (R9.2)
AR_GPIO_2: PROC011B_DUT (U2.K13), PROC011B_Pwr_RST_LEDs (R110.2 R116.1), PROC011B_LP Connector (R8.2)
AR_HOSTINTR1: PROC011B_DUT (U2.P13), PROC011B_LP Connector (R10.2 R13.2), PROC011B_HD Connector (R64.2)
AR_LVDS_0_N: PROC011B_DUT (U2.J15), PROC011B_HD Connector (R48.2)
AR_LVDS_0_P: PROC011B_DUT (U2.J14), PROC011B_HD Connector (R49.2)
AR_LVDS_1_N: PROC011B_DUT (U2.K15), PROC011B_HD Connector (R50.2)
AR_LVDS_1_P: PROC011B_DUT (U2.K14), PROC011B_HD Connector (R51.2)
AR_LVDS_CLK_N: PROC011B_DUT (U2.L15), PROC011B_HD Connector (R52.2)
AR_LVDS_CLK_P: PROC011B_DUT (U2.L14), PROC011B_HD Connector (R53.2)
AR_LVDS_FRCLK_N: PROC011B_DUT (U2.M15), PROC011B_HD Connector (R58.2)
AR_LVDS_FRCLK_P: PROC011B_DUT (U2.M14), PROC011B_HD Connector (R59.2)
AR_MCUCLKOUT: PROC011B_DUT (U2.N8), PROC011B_LP Connector (R25.1)
AR_MISO1: PROC011B_DUT (U2.E14), PROC011B_CAN Interface (U14.2)
AR_MOSI1: PROC011B_DUT (U2.D13), PROC011B_CAN Interface (U14.5)
AR_MSS_LOGGER: PROC011B_DUT (U2.F14), PROC011B_LP Connector (R26.1), PROC011B_XDS110 Interface_1B (R136.1)
AR_NERR_OUT: PROC011B_DUT (U2.N6), PROC011B_Pwr_RST_LEDs (DS1.2 R91.1), PROC011B_LP Connector (R19.1), PROC011B_HD Connector (R63.2)
AR_NERRIN: PROC011B_DUT (U2.N7), PROC011B_LP Connector (R16.1 R24.1)
AR_NRST: PROC011B_DUT (U2.R3), PROC011B_Pwr_RST_LEDs (6 pins)
AR_NRST_MCU: PROC011B_Pwr_RST_LEDs (R77.1), PROC011B_LP Connector (R2.2), PROC011B_HD Connector (R20.1)
AR_NRST_XDS: PROC011B_Pwr_RST_LEDs (R80.1), PROC011B_XDS110 Interface_1B (U6.40)
AR_OSC_CLKOUT: PROC011B_DUT (U2.A14), PROC011B_HD Connector (R111.1)
AR_PMIC_CLKOUT_SOP2: PROC011B_DUT (U2.P9), PROC011B_LP Connector (R109.2), PROC011B_SOP selection (R97.1 R98.1)
AR_QSPI_CS: PROC011B_DUT (U2.P11), PROC011B_QSPI flash section (R38.1 U1.1)
AR_QSPI_D0: PROC011B_DUT (U2.R13), PROC011B_QSPI flash section (R45.2)
AR_QSPI_D1: PROC011B_DUT (U2.N12), PROC011B_QSPI flash section (R39.1)
AR_QSPI_D2: PROC011B_DUT (U2.R14), PROC011B_QSPI flash section (R42.1 R43.1)
AR_QSPI_D3: PROC011B_DUT (U2.P12), PROC011B_QSPI flash section (R40.2 R41.1)
AR_QSPI_SCLK: PROC011B_DUT (U2.R12), PROC011B_QSPI flash section (R44.2)
AR_RS232RX: PROC011B_DUT (U2.N4), PROC011B_LP Connector (R166.1 R172.1), PROC011B_HD Connector (R33.1), PROC011B_XDS110 Interface_1B (R129.1)
AR_RS232TX: PROC011B_DUT (U2.N5), PROC011B_LP Connector (R169.1 R173.1), PROC011B_HD Connector (R21.1), PROC011B_XDS110 Interface_1B (R128.1)
AR_SCL: PROC011B_DUT (R210.1), PROC011B_PMIC (R146.1), PROC011B_LP Connector (R163.1 R171.1), PROC011B_HD Connector (R22.1), PROC011B_Tempsensor (R5.1 R198.1)
AR_SDA: PROC011B_DUT (R211.1), PROC011B_PMIC (R144.2), PROC011B_LP Connector (R162.1 R170.1), PROC011B_HD Connector (R23.1), PROC011B_Tempsensor (R168.2 R199.2)
AR_SPICLK1: PROC011B_DUT (U2.E13), PROC011B_CAN Interface (U14.7)
AR_SYNC_IN: PROC011B_DUT (U2.P4), PROC011B_LP Connector (R165.1), PROC011B_HD Connector (R62.2)
AR_SYNC_OUT_SOP1: PROC011B_DUT (U2.G13), PROC011B_LP Connector (R108.2), PROC011B_SOP selection (R113.1)
AR_TCK: PROC011B_DUT (U2.P10), PROC011B_HD Connector (R66.2 R70.1)
AR_TDI: PROC011B_DUT (U2.R11), PROC011B_HD Connector (R29.1 R30.1)
AR_TDO_SOP0: PROC011B_DUT (U2.N13), PROC011B_HD Connector (R67.2 R71.1), PROC011B_SOP selection (R89.1)
AR_TMS: PROC011B_DUT (U2.N10), PROC011B_HD Connector (R65.2 R69.1)
AR_VSENSE: PROC011B_DUT (U2.C14), PROC011B_LP Connector (P1.1)
AR_WARMRST: PROC011B_DUT (U2.N9), PROC011B_LP Connector (R15.1 R18.1)
CS1: PROC011B_LP Connector (R1.2 R14.1), PROC011B_HD Connector (R17.1), PROC011B_CAN Interface (U14.11)
MCU_SOP0: PROC011B_LP Connector (R36.1), PROC011B_SOP selection (R93.2)
MCU_SOP1: PROC011B_LP Connector (R35.1), PROC011B_SOP selection (R112.2)
MCU_SOP2: PROC011B_LP Connector (R32.1), PROC011B_SOP selection (R101.2)
MISO1: PROC011B_LP Connector (R6.2), PROC011B_HD Connector (R7.2), PROC011B_CAN Interface (U14.1)
MOSI1: PROC011B_LP Connector (R4.2), PROC011B_HD Connector (R28.1), PROC011B_CAN Interface (U14.4)
PGOOD: PROC011B_PMIC (R138.2 R141.2), PROC011B_LP Connector (R107.2), PROC011B_HD Connector (R27.1), PROC011B_XDS110 Interface_1A (R159.1)
PMIC_CLK: PROC011B_PMIC (U8.3), PROC011B_SOP selection (R97.2)
PMIC_EN1: PROC011B_PMIC (R142.1 U8.7), PROC011B_LP Connector (R102.2)
SPICLK1: PROC011B_LP Connector (R76.1), PROC011B_HD Connector (R75.1), PROC011B_CAN Interface (U14.8)
VBUS_1_DETECT: PROC011B_XDS110 Interface_1A (C69.2 R151.1 R153.2), PROC011B_XDS110 Interface_1B (U6.1)
XDSET_1_D_N: PROC011B_XDS110 Interface_1A (J8.2 U10.1), PROC011B_XDS110 Interface_1B (U6.93)
XDSET_1_D_P: PROC011B_XDS110 Interface_1A (J8.3 U10.4), PROC011B_XDS110 Interface_1B (U6.94)
XDSET_1_ID: PROC011B_XDS110 Interface_1A (J8.4 U10.2), PROC011B_XDS110 Interface_1B (R152.2)
XDSET_TCK: PROC011B_HD Connector (R70.2), PROC011B_XDS110 Interface_1B (U6.35)
XDSET_TDI: PROC011B_HD Connector (R30.2), PROC011B_XDS110 Interface_1B (U6.38)
XDSET_TDO: PROC011B_HD Connector (R71.2), PROC011B_XDS110 Interface_1B (U6.37)
XDSET_TMS: PROC011B_HD Connector (R69.2), PROC011B_XDS110 Interface_1B (U6.36)

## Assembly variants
001: not fitted C83 FB2 FID1 FID2 FID3 FID4 FID5 FID6 FID7 L5 L6 R8 R9 R21 R26 R33 R47 R83 R97 R102 R108 R109 R115 R120 R130 R135 R137 R164 R166 R169 R177 R178 R195 R210 R211
002: not fitted C83 FB2 FID1 FID2 FID3 FID4 FID5 FID6 FID7 L5 L6 R8 R9 R21 R26 R33 R47 R83 R97 R102 R108 R109 R115 R120 R130 R135 R137 R164 R166 R169 R177 R178 R195 R210 R211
